VERSION 5.7 ;
  NOWIREEXTENSIONATPIN ON ;
  DIVIDERCHAR "/" ;
  BUSBITCHARS "[]" ;
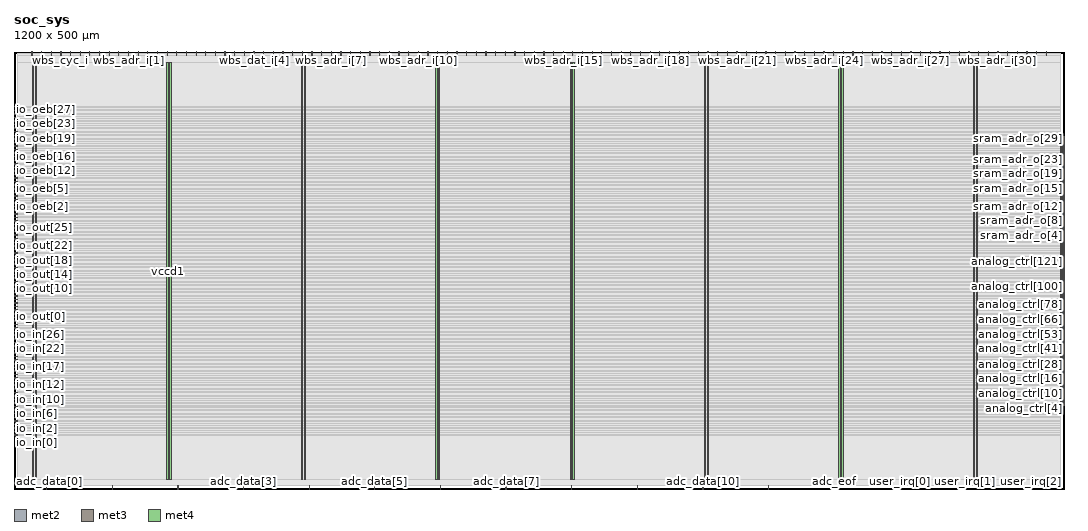
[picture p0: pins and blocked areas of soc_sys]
MACRO soc_sys
  CLASS BLOCK ;
  FOREIGN soc_sys ;
  ORIGIN 0.000 0.000 ;
  SIZE 1200.000 BY 500.000 ;
  PIN adc_data[0]
    DIRECTION INPUT ;
    USE SIGNAL ;
    ANTENNAGATEAREA 0.852000 ;
    PORT
      LAYER met2 ;
        RECT 37.350 0.000 37.630 4.000 ;
    END
  END adc_data[0]
  PIN adc_data[10]
    DIRECTION INPUT ;
    USE SIGNAL ;
    ANTENNAGATEAREA 0.247500 ;
    PORT
      LAYER met2 ;
        RECT 787.150 0.000 787.430 4.000 ;
    END
  END adc_data[10]
  PIN adc_data[11]
    DIRECTION INPUT ;
    USE SIGNAL ;
    ANTENNAGATEAREA 0.213000 ;
    PORT
      LAYER met2 ;
        RECT 862.130 0.000 862.410 4.000 ;
    END
  END adc_data[11]
  PIN adc_data[1]
    DIRECTION INPUT ;
    USE SIGNAL ;
    ANTENNAGATEAREA 0.742500 ;
    PORT
      LAYER met2 ;
        RECT 112.330 0.000 112.610 4.000 ;
    END
  END adc_data[1]
  PIN adc_data[2]
    DIRECTION INPUT ;
    USE SIGNAL ;
    ANTENNAGATEAREA 0.742500 ;
    PORT
      LAYER met2 ;
        RECT 187.310 0.000 187.590 4.000 ;
    END
  END adc_data[2]
  PIN adc_data[3]
    DIRECTION INPUT ;
    USE SIGNAL ;
    ANTENNAGATEAREA 0.742500 ;
    PORT
      LAYER met2 ;
        RECT 262.290 0.000 262.570 4.000 ;
    END
  END adc_data[3]
  PIN adc_data[4]
    DIRECTION INPUT ;
    USE SIGNAL ;
    ANTENNAGATEAREA 0.742500 ;
    PORT
      LAYER met2 ;
        RECT 337.270 0.000 337.550 4.000 ;
    END
  END adc_data[4]
  PIN adc_data[5]
    DIRECTION INPUT ;
    USE SIGNAL ;
    ANTENNAGATEAREA 0.495000 ;
    PORT
      LAYER met2 ;
        RECT 412.250 0.000 412.530 4.000 ;
    END
  END adc_data[5]
  PIN adc_data[6]
    DIRECTION INPUT ;
    USE SIGNAL ;
    ANTENNAGATEAREA 0.495000 ;
    PORT
      LAYER met2 ;
        RECT 487.230 0.000 487.510 4.000 ;
    END
  END adc_data[6]
  PIN adc_data[7]
    DIRECTION INPUT ;
    USE SIGNAL ;
    ANTENNAGATEAREA 0.426000 ;
    PORT
      LAYER met2 ;
        RECT 562.210 0.000 562.490 4.000 ;
    END
  END adc_data[7]
  PIN adc_data[8]
    DIRECTION INPUT ;
    USE SIGNAL ;
    ANTENNAGATEAREA 0.426000 ;
    PORT
      LAYER met2 ;
        RECT 637.190 0.000 637.470 4.000 ;
    END
  END adc_data[8]
  PIN adc_data[9]
    DIRECTION INPUT ;
    USE SIGNAL ;
    ANTENNAGATEAREA 0.247500 ;
    PORT
      LAYER met2 ;
        RECT 712.170 0.000 712.450 4.000 ;
    END
  END adc_data[9]
  PIN adc_eof
    DIRECTION INPUT ;
    USE SIGNAL ;
    ANTENNAGATEAREA 0.159000 ;
    PORT
      LAYER met2 ;
        RECT 937.110 0.000 937.390 4.000 ;
    END
  END adc_eof
  PIN analog_ctrl[0]
    DIRECTION OUTPUT ;
    USE SIGNAL ;
    ANTENNADIFFAREA 2.673000 ;
    PORT
      LAYER met3 ;
        RECT 1196.000 95.240 1200.000 95.840 ;
    END
  END analog_ctrl[0]
  PIN analog_ctrl[100]
    DIRECTION OUTPUT ;
    USE SIGNAL ;
    PORT
      LAYER met3 ;
        RECT 1196.000 231.240 1200.000 231.840 ;
    END
  END analog_ctrl[100]
  PIN analog_ctrl[101]
    DIRECTION OUTPUT ;
    USE SIGNAL ;
    PORT
      LAYER met3 ;
        RECT 1196.000 232.600 1200.000 233.200 ;
    END
  END analog_ctrl[101]
  PIN analog_ctrl[102]
    DIRECTION OUTPUT ;
    USE SIGNAL ;
    PORT
      LAYER met3 ;
        RECT 1196.000 233.960 1200.000 234.560 ;
    END
  END analog_ctrl[102]
  PIN analog_ctrl[103]
    DIRECTION OUTPUT ;
    USE SIGNAL ;
    PORT
      LAYER met3 ;
        RECT 1196.000 235.320 1200.000 235.920 ;
    END
  END analog_ctrl[103]
  PIN analog_ctrl[104]
    DIRECTION OUTPUT ;
    USE SIGNAL ;
    ANTENNADIFFAREA 2.673000 ;
    PORT
      LAYER met3 ;
        RECT 1196.000 236.680 1200.000 237.280 ;
    END
  END analog_ctrl[104]
  PIN analog_ctrl[105]
    DIRECTION OUTPUT ;
    USE SIGNAL ;
    ANTENNADIFFAREA 2.673000 ;
    PORT
      LAYER met3 ;
        RECT 1196.000 238.040 1200.000 238.640 ;
    END
  END analog_ctrl[105]
  PIN analog_ctrl[106]
    DIRECTION OUTPUT ;
    USE SIGNAL ;
    ANTENNADIFFAREA 2.673000 ;
    PORT
      LAYER met3 ;
        RECT 1196.000 239.400 1200.000 240.000 ;
    END
  END analog_ctrl[106]
  PIN analog_ctrl[107]
    DIRECTION OUTPUT ;
    USE SIGNAL ;
    ANTENNADIFFAREA 2.673000 ;
    PORT
      LAYER met3 ;
        RECT 1196.000 240.760 1200.000 241.360 ;
    END
  END analog_ctrl[107]
  PIN analog_ctrl[108]
    DIRECTION OUTPUT ;
    USE SIGNAL ;
    ANTENNADIFFAREA 2.673000 ;
    PORT
      LAYER met3 ;
        RECT 1196.000 242.120 1200.000 242.720 ;
    END
  END analog_ctrl[108]
  PIN analog_ctrl[109]
    DIRECTION OUTPUT ;
    USE SIGNAL ;
    ANTENNADIFFAREA 2.673000 ;
    PORT
      LAYER met3 ;
        RECT 1196.000 243.480 1200.000 244.080 ;
    END
  END analog_ctrl[109]
  PIN analog_ctrl[10]
    DIRECTION OUTPUT ;
    USE SIGNAL ;
    ANTENNADIFFAREA 2.673000 ;
    PORT
      LAYER met3 ;
        RECT 1196.000 108.840 1200.000 109.440 ;
    END
  END analog_ctrl[10]
  PIN analog_ctrl[110]
    DIRECTION OUTPUT ;
    USE SIGNAL ;
    ANTENNADIFFAREA 2.673000 ;
    PORT
      LAYER met3 ;
        RECT 1196.000 244.840 1200.000 245.440 ;
    END
  END analog_ctrl[110]
  PIN analog_ctrl[111]
    DIRECTION OUTPUT ;
    USE SIGNAL ;
    ANTENNADIFFAREA 2.673000 ;
    PORT
      LAYER met3 ;
        RECT 1196.000 246.200 1200.000 246.800 ;
    END
  END analog_ctrl[111]
  PIN analog_ctrl[112]
    DIRECTION OUTPUT ;
    USE SIGNAL ;
    ANTENNADIFFAREA 2.673000 ;
    PORT
      LAYER met3 ;
        RECT 1196.000 247.560 1200.000 248.160 ;
    END
  END analog_ctrl[112]
  PIN analog_ctrl[113]
    DIRECTION OUTPUT ;
    USE SIGNAL ;
    ANTENNADIFFAREA 2.673000 ;
    PORT
      LAYER met3 ;
        RECT 1196.000 248.920 1200.000 249.520 ;
    END
  END analog_ctrl[113]
  PIN analog_ctrl[114]
    DIRECTION OUTPUT ;
    USE SIGNAL ;
    ANTENNADIFFAREA 2.673000 ;
    PORT
      LAYER met3 ;
        RECT 1196.000 250.280 1200.000 250.880 ;
    END
  END analog_ctrl[114]
  PIN analog_ctrl[115]
    DIRECTION OUTPUT ;
    USE SIGNAL ;
    ANTENNADIFFAREA 2.673000 ;
    PORT
      LAYER met3 ;
        RECT 1196.000 251.640 1200.000 252.240 ;
    END
  END analog_ctrl[115]
  PIN analog_ctrl[116]
    DIRECTION OUTPUT ;
    USE SIGNAL ;
    ANTENNADIFFAREA 2.673000 ;
    PORT
      LAYER met3 ;
        RECT 1196.000 253.000 1200.000 253.600 ;
    END
  END analog_ctrl[116]
  PIN analog_ctrl[117]
    DIRECTION OUTPUT ;
    USE SIGNAL ;
    ANTENNADIFFAREA 2.673000 ;
    PORT
      LAYER met3 ;
        RECT 1196.000 254.360 1200.000 254.960 ;
    END
  END analog_ctrl[117]
  PIN analog_ctrl[118]
    DIRECTION OUTPUT ;
    USE SIGNAL ;
    ANTENNADIFFAREA 2.673000 ;
    PORT
      LAYER met3 ;
        RECT 1196.000 255.720 1200.000 256.320 ;
    END
  END analog_ctrl[118]
  PIN analog_ctrl[119]
    DIRECTION OUTPUT ;
    USE SIGNAL ;
    ANTENNADIFFAREA 2.673000 ;
    PORT
      LAYER met3 ;
        RECT 1196.000 257.080 1200.000 257.680 ;
    END
  END analog_ctrl[119]
  PIN analog_ctrl[11]
    DIRECTION OUTPUT ;
    USE SIGNAL ;
    ANTENNADIFFAREA 2.673000 ;
    PORT
      LAYER met3 ;
        RECT 1196.000 110.200 1200.000 110.800 ;
    END
  END analog_ctrl[11]
  PIN analog_ctrl[120]
    DIRECTION OUTPUT ;
    USE SIGNAL ;
    ANTENNADIFFAREA 2.673000 ;
    PORT
      LAYER met3 ;
        RECT 1196.000 258.440 1200.000 259.040 ;
    END
  END analog_ctrl[120]
  PIN analog_ctrl[121]
    DIRECTION OUTPUT ;
    USE SIGNAL ;
    ANTENNADIFFAREA 2.673000 ;
    PORT
      LAYER met3 ;
        RECT 1196.000 259.800 1200.000 260.400 ;
    END
  END analog_ctrl[121]
  PIN analog_ctrl[122]
    DIRECTION OUTPUT ;
    USE SIGNAL ;
    ANTENNADIFFAREA 2.673000 ;
    PORT
      LAYER met3 ;
        RECT 1196.000 261.160 1200.000 261.760 ;
    END
  END analog_ctrl[122]
  PIN analog_ctrl[12]
    DIRECTION OUTPUT ;
    USE SIGNAL ;
    ANTENNADIFFAREA 2.673000 ;
    PORT
      LAYER met3 ;
        RECT 1196.000 111.560 1200.000 112.160 ;
    END
  END analog_ctrl[12]
  PIN analog_ctrl[13]
    DIRECTION OUTPUT ;
    USE SIGNAL ;
    ANTENNADIFFAREA 2.673000 ;
    PORT
      LAYER met3 ;
        RECT 1196.000 112.920 1200.000 113.520 ;
    END
  END analog_ctrl[13]
  PIN analog_ctrl[14]
    DIRECTION OUTPUT ;
    USE SIGNAL ;
    ANTENNADIFFAREA 2.673000 ;
    PORT
      LAYER met3 ;
        RECT 1196.000 114.280 1200.000 114.880 ;
    END
  END analog_ctrl[14]
  PIN analog_ctrl[15]
    DIRECTION OUTPUT ;
    USE SIGNAL ;
    ANTENNADIFFAREA 2.673000 ;
    PORT
      LAYER met3 ;
        RECT 1196.000 115.640 1200.000 116.240 ;
    END
  END analog_ctrl[15]
  PIN analog_ctrl[16]
    DIRECTION OUTPUT ;
    USE SIGNAL ;
    ANTENNADIFFAREA 2.673000 ;
    PORT
      LAYER met3 ;
        RECT 1196.000 117.000 1200.000 117.600 ;
    END
  END analog_ctrl[16]
  PIN analog_ctrl[17]
    DIRECTION OUTPUT ;
    USE SIGNAL ;
    ANTENNADIFFAREA 2.673000 ;
    PORT
      LAYER met3 ;
        RECT 1196.000 118.360 1200.000 118.960 ;
    END
  END analog_ctrl[17]
  PIN analog_ctrl[18]
    DIRECTION OUTPUT ;
    USE SIGNAL ;
    ANTENNADIFFAREA 2.673000 ;
    PORT
      LAYER met3 ;
        RECT 1196.000 119.720 1200.000 120.320 ;
    END
  END analog_ctrl[18]
  PIN analog_ctrl[19]
    DIRECTION OUTPUT ;
    USE SIGNAL ;
    ANTENNADIFFAREA 2.673000 ;
    PORT
      LAYER met3 ;
        RECT 1196.000 121.080 1200.000 121.680 ;
    END
  END analog_ctrl[19]
  PIN analog_ctrl[1]
    DIRECTION OUTPUT ;
    USE SIGNAL ;
    ANTENNADIFFAREA 2.673000 ;
    PORT
      LAYER met3 ;
        RECT 1196.000 96.600 1200.000 97.200 ;
    END
  END analog_ctrl[1]
  PIN analog_ctrl[20]
    DIRECTION OUTPUT ;
    USE SIGNAL ;
    ANTENNADIFFAREA 2.673000 ;
    PORT
      LAYER met3 ;
        RECT 1196.000 122.440 1200.000 123.040 ;
    END
  END analog_ctrl[20]
  PIN analog_ctrl[21]
    DIRECTION OUTPUT ;
    USE SIGNAL ;
    ANTENNADIFFAREA 2.673000 ;
    PORT
      LAYER met3 ;
        RECT 1196.000 123.800 1200.000 124.400 ;
    END
  END analog_ctrl[21]
  PIN analog_ctrl[22]
    DIRECTION OUTPUT ;
    USE SIGNAL ;
    ANTENNADIFFAREA 2.673000 ;
    PORT
      LAYER met3 ;
        RECT 1196.000 125.160 1200.000 125.760 ;
    END
  END analog_ctrl[22]
  PIN analog_ctrl[23]
    DIRECTION OUTPUT ;
    USE SIGNAL ;
    ANTENNADIFFAREA 2.673000 ;
    PORT
      LAYER met3 ;
        RECT 1196.000 126.520 1200.000 127.120 ;
    END
  END analog_ctrl[23]
  PIN analog_ctrl[24]
    DIRECTION OUTPUT ;
    USE SIGNAL ;
    ANTENNADIFFAREA 2.673000 ;
    PORT
      LAYER met3 ;
        RECT 1196.000 127.880 1200.000 128.480 ;
    END
  END analog_ctrl[24]
  PIN analog_ctrl[25]
    DIRECTION OUTPUT ;
    USE SIGNAL ;
    ANTENNADIFFAREA 2.673000 ;
    PORT
      LAYER met3 ;
        RECT 1196.000 129.240 1200.000 129.840 ;
    END
  END analog_ctrl[25]
  PIN analog_ctrl[26]
    DIRECTION OUTPUT ;
    USE SIGNAL ;
    ANTENNADIFFAREA 2.673000 ;
    PORT
      LAYER met3 ;
        RECT 1196.000 130.600 1200.000 131.200 ;
    END
  END analog_ctrl[26]
  PIN analog_ctrl[27]
    DIRECTION OUTPUT ;
    USE SIGNAL ;
    ANTENNADIFFAREA 2.673000 ;
    PORT
      LAYER met3 ;
        RECT 1196.000 131.960 1200.000 132.560 ;
    END
  END analog_ctrl[27]
  PIN analog_ctrl[28]
    DIRECTION OUTPUT ;
    USE SIGNAL ;
    ANTENNADIFFAREA 2.673000 ;
    PORT
      LAYER met3 ;
        RECT 1196.000 133.320 1200.000 133.920 ;
    END
  END analog_ctrl[28]
  PIN analog_ctrl[29]
    DIRECTION OUTPUT ;
    USE SIGNAL ;
    ANTENNADIFFAREA 2.673000 ;
    PORT
      LAYER met3 ;
        RECT 1196.000 134.680 1200.000 135.280 ;
    END
  END analog_ctrl[29]
  PIN analog_ctrl[2]
    DIRECTION OUTPUT ;
    USE SIGNAL ;
    ANTENNADIFFAREA 2.673000 ;
    PORT
      LAYER met3 ;
        RECT 1196.000 97.960 1200.000 98.560 ;
    END
  END analog_ctrl[2]
  PIN analog_ctrl[30]
    DIRECTION OUTPUT ;
    USE SIGNAL ;
    ANTENNADIFFAREA 2.673000 ;
    PORT
      LAYER met3 ;
        RECT 1196.000 136.040 1200.000 136.640 ;
    END
  END analog_ctrl[30]
  PIN analog_ctrl[31]
    DIRECTION OUTPUT ;
    USE SIGNAL ;
    ANTENNADIFFAREA 2.673000 ;
    PORT
      LAYER met3 ;
        RECT 1196.000 137.400 1200.000 138.000 ;
    END
  END analog_ctrl[31]
  PIN analog_ctrl[32]
    DIRECTION OUTPUT ;
    USE SIGNAL ;
    ANTENNADIFFAREA 2.673000 ;
    PORT
      LAYER met3 ;
        RECT 1196.000 138.760 1200.000 139.360 ;
    END
  END analog_ctrl[32]
  PIN analog_ctrl[33]
    DIRECTION OUTPUT ;
    USE SIGNAL ;
    ANTENNADIFFAREA 2.673000 ;
    PORT
      LAYER met3 ;
        RECT 1196.000 140.120 1200.000 140.720 ;
    END
  END analog_ctrl[33]
  PIN analog_ctrl[34]
    DIRECTION OUTPUT ;
    USE SIGNAL ;
    ANTENNADIFFAREA 2.673000 ;
    PORT
      LAYER met3 ;
        RECT 1196.000 141.480 1200.000 142.080 ;
    END
  END analog_ctrl[34]
  PIN analog_ctrl[35]
    DIRECTION OUTPUT ;
    USE SIGNAL ;
    ANTENNADIFFAREA 2.673000 ;
    PORT
      LAYER met3 ;
        RECT 1196.000 142.840 1200.000 143.440 ;
    END
  END analog_ctrl[35]
  PIN analog_ctrl[36]
    DIRECTION OUTPUT ;
    USE SIGNAL ;
    ANTENNADIFFAREA 2.673000 ;
    PORT
      LAYER met3 ;
        RECT 1196.000 144.200 1200.000 144.800 ;
    END
  END analog_ctrl[36]
  PIN analog_ctrl[37]
    DIRECTION OUTPUT ;
    USE SIGNAL ;
    ANTENNADIFFAREA 2.673000 ;
    PORT
      LAYER met3 ;
        RECT 1196.000 145.560 1200.000 146.160 ;
    END
  END analog_ctrl[37]
  PIN analog_ctrl[38]
    DIRECTION OUTPUT ;
    USE SIGNAL ;
    ANTENNADIFFAREA 2.673000 ;
    PORT
      LAYER met3 ;
        RECT 1196.000 146.920 1200.000 147.520 ;
    END
  END analog_ctrl[38]
  PIN analog_ctrl[39]
    DIRECTION OUTPUT ;
    USE SIGNAL ;
    ANTENNADIFFAREA 2.673000 ;
    PORT
      LAYER met3 ;
        RECT 1196.000 148.280 1200.000 148.880 ;
    END
  END analog_ctrl[39]
  PIN analog_ctrl[3]
    DIRECTION OUTPUT ;
    USE SIGNAL ;
    ANTENNADIFFAREA 2.673000 ;
    PORT
      LAYER met3 ;
        RECT 1196.000 99.320 1200.000 99.920 ;
    END
  END analog_ctrl[3]
  PIN analog_ctrl[40]
    DIRECTION OUTPUT ;
    USE SIGNAL ;
    ANTENNADIFFAREA 2.673000 ;
    PORT
      LAYER met3 ;
        RECT 1196.000 149.640 1200.000 150.240 ;
    END
  END analog_ctrl[40]
  PIN analog_ctrl[41]
    DIRECTION OUTPUT ;
    USE SIGNAL ;
    ANTENNADIFFAREA 2.673000 ;
    PORT
      LAYER met3 ;
        RECT 1196.000 151.000 1200.000 151.600 ;
    END
  END analog_ctrl[41]
  PIN analog_ctrl[42]
    DIRECTION OUTPUT ;
    USE SIGNAL ;
    ANTENNADIFFAREA 2.673000 ;
    PORT
      LAYER met3 ;
        RECT 1196.000 152.360 1200.000 152.960 ;
    END
  END analog_ctrl[42]
  PIN analog_ctrl[43]
    DIRECTION OUTPUT ;
    USE SIGNAL ;
    ANTENNADIFFAREA 2.673000 ;
    PORT
      LAYER met3 ;
        RECT 1196.000 153.720 1200.000 154.320 ;
    END
  END analog_ctrl[43]
  PIN analog_ctrl[44]
    DIRECTION OUTPUT ;
    USE SIGNAL ;
    ANTENNADIFFAREA 2.673000 ;
    PORT
      LAYER met3 ;
        RECT 1196.000 155.080 1200.000 155.680 ;
    END
  END analog_ctrl[44]
  PIN analog_ctrl[45]
    DIRECTION OUTPUT ;
    USE SIGNAL ;
    ANTENNADIFFAREA 2.673000 ;
    PORT
      LAYER met3 ;
        RECT 1196.000 156.440 1200.000 157.040 ;
    END
  END analog_ctrl[45]
  PIN analog_ctrl[46]
    DIRECTION OUTPUT ;
    USE SIGNAL ;
    ANTENNADIFFAREA 2.673000 ;
    PORT
      LAYER met3 ;
        RECT 1196.000 157.800 1200.000 158.400 ;
    END
  END analog_ctrl[46]
  PIN analog_ctrl[47]
    DIRECTION OUTPUT ;
    USE SIGNAL ;
    ANTENNADIFFAREA 2.673000 ;
    PORT
      LAYER met3 ;
        RECT 1196.000 159.160 1200.000 159.760 ;
    END
  END analog_ctrl[47]
  PIN analog_ctrl[48]
    DIRECTION OUTPUT ;
    USE SIGNAL ;
    ANTENNADIFFAREA 2.673000 ;
    PORT
      LAYER met3 ;
        RECT 1196.000 160.520 1200.000 161.120 ;
    END
  END analog_ctrl[48]
  PIN analog_ctrl[49]
    DIRECTION OUTPUT ;
    USE SIGNAL ;
    ANTENNADIFFAREA 2.673000 ;
    PORT
      LAYER met3 ;
        RECT 1196.000 161.880 1200.000 162.480 ;
    END
  END analog_ctrl[49]
  PIN analog_ctrl[4]
    DIRECTION OUTPUT ;
    USE SIGNAL ;
    ANTENNADIFFAREA 2.673000 ;
    PORT
      LAYER met3 ;
        RECT 1196.000 100.680 1200.000 101.280 ;
    END
  END analog_ctrl[4]
  PIN analog_ctrl[50]
    DIRECTION OUTPUT ;
    USE SIGNAL ;
    ANTENNADIFFAREA 2.673000 ;
    PORT
      LAYER met3 ;
        RECT 1196.000 163.240 1200.000 163.840 ;
    END
  END analog_ctrl[50]
  PIN analog_ctrl[51]
    DIRECTION OUTPUT ;
    USE SIGNAL ;
    ANTENNADIFFAREA 2.673000 ;
    PORT
      LAYER met3 ;
        RECT 1196.000 164.600 1200.000 165.200 ;
    END
  END analog_ctrl[51]
  PIN analog_ctrl[52]
    DIRECTION OUTPUT ;
    USE SIGNAL ;
    ANTENNADIFFAREA 2.673000 ;
    PORT
      LAYER met3 ;
        RECT 1196.000 165.960 1200.000 166.560 ;
    END
  END analog_ctrl[52]
  PIN analog_ctrl[53]
    DIRECTION OUTPUT ;
    USE SIGNAL ;
    ANTENNADIFFAREA 2.673000 ;
    PORT
      LAYER met3 ;
        RECT 1196.000 167.320 1200.000 167.920 ;
    END
  END analog_ctrl[53]
  PIN analog_ctrl[54]
    DIRECTION OUTPUT ;
    USE SIGNAL ;
    ANTENNADIFFAREA 2.673000 ;
    PORT
      LAYER met3 ;
        RECT 1196.000 168.680 1200.000 169.280 ;
    END
  END analog_ctrl[54]
  PIN analog_ctrl[55]
    DIRECTION OUTPUT ;
    USE SIGNAL ;
    ANTENNADIFFAREA 2.673000 ;
    PORT
      LAYER met3 ;
        RECT 1196.000 170.040 1200.000 170.640 ;
    END
  END analog_ctrl[55]
  PIN analog_ctrl[56]
    DIRECTION OUTPUT ;
    USE SIGNAL ;
    ANTENNADIFFAREA 2.673000 ;
    PORT
      LAYER met3 ;
        RECT 1196.000 171.400 1200.000 172.000 ;
    END
  END analog_ctrl[56]
  PIN analog_ctrl[57]
    DIRECTION OUTPUT ;
    USE SIGNAL ;
    ANTENNADIFFAREA 2.673000 ;
    PORT
      LAYER met3 ;
        RECT 1196.000 172.760 1200.000 173.360 ;
    END
  END analog_ctrl[57]
  PIN analog_ctrl[58]
    DIRECTION OUTPUT ;
    USE SIGNAL ;
    ANTENNADIFFAREA 2.673000 ;
    PORT
      LAYER met3 ;
        RECT 1196.000 174.120 1200.000 174.720 ;
    END
  END analog_ctrl[58]
  PIN analog_ctrl[59]
    DIRECTION OUTPUT ;
    USE SIGNAL ;
    ANTENNADIFFAREA 2.673000 ;
    PORT
      LAYER met3 ;
        RECT 1196.000 175.480 1200.000 176.080 ;
    END
  END analog_ctrl[59]
  PIN analog_ctrl[5]
    DIRECTION OUTPUT ;
    USE SIGNAL ;
    ANTENNADIFFAREA 2.673000 ;
    PORT
      LAYER met3 ;
        RECT 1196.000 102.040 1200.000 102.640 ;
    END
  END analog_ctrl[5]
  PIN analog_ctrl[60]
    DIRECTION OUTPUT ;
    USE SIGNAL ;
    ANTENNADIFFAREA 2.673000 ;
    PORT
      LAYER met3 ;
        RECT 1196.000 176.840 1200.000 177.440 ;
    END
  END analog_ctrl[60]
  PIN analog_ctrl[61]
    DIRECTION OUTPUT ;
    USE SIGNAL ;
    ANTENNADIFFAREA 2.673000 ;
    PORT
      LAYER met3 ;
        RECT 1196.000 178.200 1200.000 178.800 ;
    END
  END analog_ctrl[61]
  PIN analog_ctrl[62]
    DIRECTION OUTPUT ;
    USE SIGNAL ;
    ANTENNADIFFAREA 2.673000 ;
    PORT
      LAYER met3 ;
        RECT 1196.000 179.560 1200.000 180.160 ;
    END
  END analog_ctrl[62]
  PIN analog_ctrl[63]
    DIRECTION OUTPUT ;
    USE SIGNAL ;
    ANTENNADIFFAREA 2.673000 ;
    PORT
      LAYER met3 ;
        RECT 1196.000 180.920 1200.000 181.520 ;
    END
  END analog_ctrl[63]
  PIN analog_ctrl[64]
    DIRECTION OUTPUT ;
    USE SIGNAL ;
    ANTENNADIFFAREA 2.673000 ;
    PORT
      LAYER met3 ;
        RECT 1196.000 182.280 1200.000 182.880 ;
    END
  END analog_ctrl[64]
  PIN analog_ctrl[65]
    DIRECTION OUTPUT ;
    USE SIGNAL ;
    ANTENNADIFFAREA 2.673000 ;
    PORT
      LAYER met3 ;
        RECT 1196.000 183.640 1200.000 184.240 ;
    END
  END analog_ctrl[65]
  PIN analog_ctrl[66]
    DIRECTION OUTPUT ;
    USE SIGNAL ;
    ANTENNADIFFAREA 2.673000 ;
    PORT
      LAYER met3 ;
        RECT 1196.000 185.000 1200.000 185.600 ;
    END
  END analog_ctrl[66]
  PIN analog_ctrl[67]
    DIRECTION OUTPUT ;
    USE SIGNAL ;
    ANTENNADIFFAREA 2.673000 ;
    PORT
      LAYER met3 ;
        RECT 1196.000 186.360 1200.000 186.960 ;
    END
  END analog_ctrl[67]
  PIN analog_ctrl[68]
    DIRECTION OUTPUT ;
    USE SIGNAL ;
    ANTENNADIFFAREA 2.673000 ;
    PORT
      LAYER met3 ;
        RECT 1196.000 187.720 1200.000 188.320 ;
    END
  END analog_ctrl[68]
  PIN analog_ctrl[69]
    DIRECTION OUTPUT ;
    USE SIGNAL ;
    ANTENNADIFFAREA 2.673000 ;
    PORT
      LAYER met3 ;
        RECT 1196.000 189.080 1200.000 189.680 ;
    END
  END analog_ctrl[69]
  PIN analog_ctrl[6]
    DIRECTION OUTPUT ;
    USE SIGNAL ;
    ANTENNADIFFAREA 2.673000 ;
    PORT
      LAYER met3 ;
        RECT 1196.000 103.400 1200.000 104.000 ;
    END
  END analog_ctrl[6]
  PIN analog_ctrl[70]
    DIRECTION OUTPUT ;
    USE SIGNAL ;
    ANTENNADIFFAREA 2.673000 ;
    PORT
      LAYER met3 ;
        RECT 1196.000 190.440 1200.000 191.040 ;
    END
  END analog_ctrl[70]
  PIN analog_ctrl[71]
    DIRECTION OUTPUT ;
    USE SIGNAL ;
    ANTENNADIFFAREA 2.673000 ;
    PORT
      LAYER met3 ;
        RECT 1196.000 191.800 1200.000 192.400 ;
    END
  END analog_ctrl[71]
  PIN analog_ctrl[72]
    DIRECTION OUTPUT ;
    USE SIGNAL ;
    ANTENNADIFFAREA 2.673000 ;
    PORT
      LAYER met3 ;
        RECT 1196.000 193.160 1200.000 193.760 ;
    END
  END analog_ctrl[72]
  PIN analog_ctrl[73]
    DIRECTION OUTPUT ;
    USE SIGNAL ;
    ANTENNADIFFAREA 2.673000 ;
    PORT
      LAYER met3 ;
        RECT 1196.000 194.520 1200.000 195.120 ;
    END
  END analog_ctrl[73]
  PIN analog_ctrl[74]
    DIRECTION OUTPUT ;
    USE SIGNAL ;
    ANTENNADIFFAREA 2.673000 ;
    PORT
      LAYER met3 ;
        RECT 1196.000 195.880 1200.000 196.480 ;
    END
  END analog_ctrl[74]
  PIN analog_ctrl[75]
    DIRECTION OUTPUT ;
    USE SIGNAL ;
    ANTENNADIFFAREA 2.673000 ;
    PORT
      LAYER met3 ;
        RECT 1196.000 197.240 1200.000 197.840 ;
    END
  END analog_ctrl[75]
  PIN analog_ctrl[76]
    DIRECTION OUTPUT ;
    USE SIGNAL ;
    ANTENNADIFFAREA 2.673000 ;
    PORT
      LAYER met3 ;
        RECT 1196.000 198.600 1200.000 199.200 ;
    END
  END analog_ctrl[76]
  PIN analog_ctrl[77]
    DIRECTION OUTPUT ;
    USE SIGNAL ;
    ANTENNADIFFAREA 2.673000 ;
    PORT
      LAYER met3 ;
        RECT 1196.000 199.960 1200.000 200.560 ;
    END
  END analog_ctrl[77]
  PIN analog_ctrl[78]
    DIRECTION OUTPUT ;
    USE SIGNAL ;
    ANTENNADIFFAREA 2.673000 ;
    PORT
      LAYER met3 ;
        RECT 1196.000 201.320 1200.000 201.920 ;
    END
  END analog_ctrl[78]
  PIN analog_ctrl[79]
    DIRECTION OUTPUT ;
    USE SIGNAL ;
    ANTENNADIFFAREA 2.673000 ;
    PORT
      LAYER met3 ;
        RECT 1196.000 202.680 1200.000 203.280 ;
    END
  END analog_ctrl[79]
  PIN analog_ctrl[7]
    DIRECTION OUTPUT ;
    USE SIGNAL ;
    PORT
      LAYER met3 ;
        RECT 1196.000 104.760 1200.000 105.360 ;
    END
  END analog_ctrl[7]
  PIN analog_ctrl[80]
    DIRECTION OUTPUT ;
    USE SIGNAL ;
    ANTENNADIFFAREA 2.673000 ;
    PORT
      LAYER met3 ;
        RECT 1196.000 204.040 1200.000 204.640 ;
    END
  END analog_ctrl[80]
  PIN analog_ctrl[81]
    DIRECTION OUTPUT ;
    USE SIGNAL ;
    ANTENNADIFFAREA 2.673000 ;
    PORT
      LAYER met3 ;
        RECT 1196.000 205.400 1200.000 206.000 ;
    END
  END analog_ctrl[81]
  PIN analog_ctrl[82]
    DIRECTION OUTPUT ;
    USE SIGNAL ;
    ANTENNADIFFAREA 2.673000 ;
    PORT
      LAYER met3 ;
        RECT 1196.000 206.760 1200.000 207.360 ;
    END
  END analog_ctrl[82]
  PIN analog_ctrl[83]
    DIRECTION OUTPUT ;
    USE SIGNAL ;
    ANTENNADIFFAREA 2.673000 ;
    PORT
      LAYER met3 ;
        RECT 1196.000 208.120 1200.000 208.720 ;
    END
  END analog_ctrl[83]
  PIN analog_ctrl[84]
    DIRECTION OUTPUT ;
    USE SIGNAL ;
    ANTENNADIFFAREA 2.673000 ;
    PORT
      LAYER met3 ;
        RECT 1196.000 209.480 1200.000 210.080 ;
    END
  END analog_ctrl[84]
  PIN analog_ctrl[85]
    DIRECTION OUTPUT ;
    USE SIGNAL ;
    ANTENNADIFFAREA 2.673000 ;
    PORT
      LAYER met3 ;
        RECT 1196.000 210.840 1200.000 211.440 ;
    END
  END analog_ctrl[85]
  PIN analog_ctrl[86]
    DIRECTION OUTPUT ;
    USE SIGNAL ;
    ANTENNADIFFAREA 2.673000 ;
    PORT
      LAYER met3 ;
        RECT 1196.000 212.200 1200.000 212.800 ;
    END
  END analog_ctrl[86]
  PIN analog_ctrl[87]
    DIRECTION OUTPUT ;
    USE SIGNAL ;
    ANTENNADIFFAREA 2.673000 ;
    PORT
      LAYER met3 ;
        RECT 1196.000 213.560 1200.000 214.160 ;
    END
  END analog_ctrl[87]
  PIN analog_ctrl[88]
    DIRECTION OUTPUT ;
    USE SIGNAL ;
    ANTENNADIFFAREA 2.673000 ;
    PORT
      LAYER met3 ;
        RECT 1196.000 214.920 1200.000 215.520 ;
    END
  END analog_ctrl[88]
  PIN analog_ctrl[89]
    DIRECTION OUTPUT ;
    USE SIGNAL ;
    ANTENNADIFFAREA 2.673000 ;
    PORT
      LAYER met3 ;
        RECT 1196.000 216.280 1200.000 216.880 ;
    END
  END analog_ctrl[89]
  PIN analog_ctrl[8]
    DIRECTION OUTPUT ;
    USE SIGNAL ;
    ANTENNADIFFAREA 2.673000 ;
    PORT
      LAYER met3 ;
        RECT 1196.000 106.120 1200.000 106.720 ;
    END
  END analog_ctrl[8]
  PIN analog_ctrl[90]
    DIRECTION OUTPUT ;
    USE SIGNAL ;
    ANTENNADIFFAREA 2.673000 ;
    PORT
      LAYER met3 ;
        RECT 1196.000 217.640 1200.000 218.240 ;
    END
  END analog_ctrl[90]
  PIN analog_ctrl[91]
    DIRECTION OUTPUT ;
    USE SIGNAL ;
    ANTENNADIFFAREA 2.673000 ;
    PORT
      LAYER met3 ;
        RECT 1196.000 219.000 1200.000 219.600 ;
    END
  END analog_ctrl[91]
  PIN analog_ctrl[92]
    DIRECTION OUTPUT ;
    USE SIGNAL ;
    ANTENNADIFFAREA 2.673000 ;
    PORT
      LAYER met3 ;
        RECT 1196.000 220.360 1200.000 220.960 ;
    END
  END analog_ctrl[92]
  PIN analog_ctrl[93]
    DIRECTION OUTPUT ;
    USE SIGNAL ;
    ANTENNADIFFAREA 2.673000 ;
    PORT
      LAYER met3 ;
        RECT 1196.000 221.720 1200.000 222.320 ;
    END
  END analog_ctrl[93]
  PIN analog_ctrl[94]
    DIRECTION OUTPUT ;
    USE SIGNAL ;
    ANTENNADIFFAREA 2.673000 ;
    PORT
      LAYER met3 ;
        RECT 1196.000 223.080 1200.000 223.680 ;
    END
  END analog_ctrl[94]
  PIN analog_ctrl[95]
    DIRECTION OUTPUT ;
    USE SIGNAL ;
    ANTENNADIFFAREA 2.673000 ;
    PORT
      LAYER met3 ;
        RECT 1196.000 224.440 1200.000 225.040 ;
    END
  END analog_ctrl[95]
  PIN analog_ctrl[96]
    DIRECTION OUTPUT ;
    USE SIGNAL ;
    ANTENNADIFFAREA 2.673000 ;
    PORT
      LAYER met3 ;
        RECT 1196.000 225.800 1200.000 226.400 ;
    END
  END analog_ctrl[96]
  PIN analog_ctrl[97]
    DIRECTION OUTPUT ;
    USE SIGNAL ;
    ANTENNADIFFAREA 2.673000 ;
    PORT
      LAYER met3 ;
        RECT 1196.000 227.160 1200.000 227.760 ;
    END
  END analog_ctrl[97]
  PIN analog_ctrl[98]
    DIRECTION OUTPUT ;
    USE SIGNAL ;
    PORT
      LAYER met3 ;
        RECT 1196.000 228.520 1200.000 229.120 ;
    END
  END analog_ctrl[98]
  PIN analog_ctrl[99]
    DIRECTION OUTPUT ;
    USE SIGNAL ;
    PORT
      LAYER met3 ;
        RECT 1196.000 229.880 1200.000 230.480 ;
    END
  END analog_ctrl[99]
  PIN analog_ctrl[9]
    DIRECTION OUTPUT ;
    USE SIGNAL ;
    ANTENNADIFFAREA 2.673000 ;
    PORT
      LAYER met3 ;
        RECT 1196.000 107.480 1200.000 108.080 ;
    END
  END analog_ctrl[9]
  PIN io_in[0]
    DIRECTION INPUT ;
    USE SIGNAL ;
    PORT
      LAYER met3 ;
        RECT 0.000 61.240 4.000 61.840 ;
    END
  END io_in[0]
  PIN io_in[10]
    DIRECTION INPUT ;
    USE SIGNAL ;
    PORT
      LAYER met3 ;
        RECT 0.000 102.040 4.000 102.640 ;
    END
  END io_in[10]
  PIN io_in[11]
    DIRECTION INPUT ;
    USE SIGNAL ;
    PORT
      LAYER met3 ;
        RECT 0.000 106.120 4.000 106.720 ;
    END
  END io_in[11]
  PIN io_in[12]
    DIRECTION INPUT ;
    USE SIGNAL ;
    PORT
      LAYER met3 ;
        RECT 0.000 110.200 4.000 110.800 ;
    END
  END io_in[12]
  PIN io_in[13]
    DIRECTION INPUT ;
    USE SIGNAL ;
    ANTENNAGATEAREA 0.426000 ;
    PORT
      LAYER met3 ;
        RECT 0.000 114.280 4.000 114.880 ;
    END
  END io_in[13]
  PIN io_in[14]
    DIRECTION INPUT ;
    USE SIGNAL ;
    ANTENNAGATEAREA 0.426000 ;
    PORT
      LAYER met3 ;
        RECT 0.000 118.360 4.000 118.960 ;
    END
  END io_in[14]
  PIN io_in[15]
    DIRECTION INPUT ;
    USE SIGNAL ;
    PORT
      LAYER met3 ;
        RECT 0.000 122.440 4.000 123.040 ;
    END
  END io_in[15]
  PIN io_in[16]
    DIRECTION INPUT ;
    USE SIGNAL ;
    ANTENNAGATEAREA 0.196500 ;
    PORT
      LAYER met3 ;
        RECT 0.000 126.520 4.000 127.120 ;
    END
  END io_in[16]
  PIN io_in[17]
    DIRECTION INPUT ;
    USE SIGNAL ;
    PORT
      LAYER met3 ;
        RECT 0.000 130.600 4.000 131.200 ;
    END
  END io_in[17]
  PIN io_in[18]
    DIRECTION INPUT ;
    USE SIGNAL ;
    PORT
      LAYER met3 ;
        RECT 0.000 134.680 4.000 135.280 ;
    END
  END io_in[18]
  PIN io_in[19]
    DIRECTION INPUT ;
    USE SIGNAL ;
    PORT
      LAYER met3 ;
        RECT 0.000 138.760 4.000 139.360 ;
    END
  END io_in[19]
  PIN io_in[1]
    DIRECTION INPUT ;
    USE SIGNAL ;
    PORT
      LAYER met3 ;
        RECT 0.000 65.320 4.000 65.920 ;
    END
  END io_in[1]
  PIN io_in[20]
    DIRECTION INPUT ;
    USE SIGNAL ;
    PORT
      LAYER met3 ;
        RECT 0.000 142.840 4.000 143.440 ;
    END
  END io_in[20]
  PIN io_in[21]
    DIRECTION INPUT ;
    USE SIGNAL ;
    PORT
      LAYER met3 ;
        RECT 0.000 146.920 4.000 147.520 ;
    END
  END io_in[21]
  PIN io_in[22]
    DIRECTION INPUT ;
    USE SIGNAL ;
    PORT
      LAYER met3 ;
        RECT 0.000 151.000 4.000 151.600 ;
    END
  END io_in[22]
  PIN io_in[23]
    DIRECTION INPUT ;
    USE SIGNAL ;
    PORT
      LAYER met3 ;
        RECT 0.000 155.080 4.000 155.680 ;
    END
  END io_in[23]
  PIN io_in[24]
    DIRECTION INPUT ;
    USE SIGNAL ;
    PORT
      LAYER met3 ;
        RECT 0.000 159.160 4.000 159.760 ;
    END
  END io_in[24]
  PIN io_in[25]
    DIRECTION INPUT ;
    USE SIGNAL ;
    PORT
      LAYER met3 ;
        RECT 0.000 163.240 4.000 163.840 ;
    END
  END io_in[25]
  PIN io_in[26]
    DIRECTION INPUT ;
    USE SIGNAL ;
    PORT
      LAYER met3 ;
        RECT 0.000 167.320 4.000 167.920 ;
    END
  END io_in[26]
  PIN io_in[27]
    DIRECTION INPUT ;
    USE SIGNAL ;
    PORT
      LAYER met3 ;
        RECT 0.000 171.400 4.000 172.000 ;
    END
  END io_in[27]
  PIN io_in[28]
    DIRECTION INPUT ;
    USE SIGNAL ;
    ANTENNAGATEAREA 0.742500 ;
    PORT
      LAYER met3 ;
        RECT 0.000 175.480 4.000 176.080 ;
    END
  END io_in[28]
  PIN io_in[29]
    DIRECTION INPUT ;
    USE SIGNAL ;
    ANTENNAGATEAREA 0.742500 ;
    PORT
      LAYER met3 ;
        RECT 0.000 179.560 4.000 180.160 ;
    END
  END io_in[29]
  PIN io_in[2]
    DIRECTION INPUT ;
    USE SIGNAL ;
    PORT
      LAYER met3 ;
        RECT 0.000 69.400 4.000 70.000 ;
    END
  END io_in[2]
  PIN io_in[30]
    DIRECTION INPUT ;
    USE SIGNAL ;
    ANTENNAGATEAREA 0.742500 ;
    PORT
      LAYER met3 ;
        RECT 0.000 183.640 4.000 184.240 ;
    END
  END io_in[30]
  PIN io_in[3]
    DIRECTION INPUT ;
    USE SIGNAL ;
    PORT
      LAYER met3 ;
        RECT 0.000 73.480 4.000 74.080 ;
    END
  END io_in[3]
  PIN io_in[4]
    DIRECTION INPUT ;
    USE SIGNAL ;
    PORT
      LAYER met3 ;
        RECT 0.000 77.560 4.000 78.160 ;
    END
  END io_in[4]
  PIN io_in[5]
    DIRECTION INPUT ;
    USE SIGNAL ;
    PORT
      LAYER met3 ;
        RECT 0.000 81.640 4.000 82.240 ;
    END
  END io_in[5]
  PIN io_in[6]
    DIRECTION INPUT ;
    USE SIGNAL ;
    PORT
      LAYER met3 ;
        RECT 0.000 85.720 4.000 86.320 ;
    END
  END io_in[6]
  PIN io_in[7]
    DIRECTION INPUT ;
    USE SIGNAL ;
    PORT
      LAYER met3 ;
        RECT 0.000 89.800 4.000 90.400 ;
    END
  END io_in[7]
  PIN io_in[8]
    DIRECTION INPUT ;
    USE SIGNAL ;
    PORT
      LAYER met3 ;
        RECT 0.000 93.880 4.000 94.480 ;
    END
  END io_in[8]
  PIN io_in[9]
    DIRECTION INPUT ;
    USE SIGNAL ;
    PORT
      LAYER met3 ;
        RECT 0.000 97.960 4.000 98.560 ;
    END
  END io_in[9]
  PIN io_oeb[0]
    DIRECTION OUTPUT ;
    USE SIGNAL ;
    PORT
      LAYER met3 ;
        RECT 0.000 314.200 4.000 314.800 ;
    END
  END io_oeb[0]
  PIN io_oeb[10]
    DIRECTION OUTPUT ;
    USE SIGNAL ;
    PORT
      LAYER met3 ;
        RECT 0.000 355.000 4.000 355.600 ;
    END
  END io_oeb[10]
  PIN io_oeb[11]
    DIRECTION OUTPUT ;
    USE SIGNAL ;
    PORT
      LAYER met3 ;
        RECT 0.000 359.080 4.000 359.680 ;
    END
  END io_oeb[11]
  PIN io_oeb[12]
    DIRECTION OUTPUT ;
    USE SIGNAL ;
    PORT
      LAYER met3 ;
        RECT 0.000 363.160 4.000 363.760 ;
    END
  END io_oeb[12]
  PIN io_oeb[13]
    DIRECTION OUTPUT ;
    USE SIGNAL ;
    ANTENNADIFFAREA 2.673000 ;
    PORT
      LAYER met3 ;
        RECT 0.000 367.240 4.000 367.840 ;
    END
  END io_oeb[13]
  PIN io_oeb[14]
    DIRECTION OUTPUT ;
    USE SIGNAL ;
    ANTENNADIFFAREA 2.673000 ;
    PORT
      LAYER met3 ;
        RECT 0.000 371.320 4.000 371.920 ;
    END
  END io_oeb[14]
  PIN io_oeb[15]
    DIRECTION OUTPUT ;
    USE SIGNAL ;
    PORT
      LAYER met3 ;
        RECT 0.000 375.400 4.000 376.000 ;
    END
  END io_oeb[15]
  PIN io_oeb[16]
    DIRECTION OUTPUT ;
    USE SIGNAL ;
    PORT
      LAYER met3 ;
        RECT 0.000 379.480 4.000 380.080 ;
    END
  END io_oeb[16]
  PIN io_oeb[17]
    DIRECTION OUTPUT ;
    USE SIGNAL ;
    PORT
      LAYER met3 ;
        RECT 0.000 383.560 4.000 384.160 ;
    END
  END io_oeb[17]
  PIN io_oeb[18]
    DIRECTION OUTPUT ;
    USE SIGNAL ;
    PORT
      LAYER met3 ;
        RECT 0.000 387.640 4.000 388.240 ;
    END
  END io_oeb[18]
  PIN io_oeb[19]
    DIRECTION OUTPUT ;
    USE SIGNAL ;
    PORT
      LAYER met3 ;
        RECT 0.000 391.720 4.000 392.320 ;
    END
  END io_oeb[19]
  PIN io_oeb[1]
    DIRECTION OUTPUT ;
    USE SIGNAL ;
    PORT
      LAYER met3 ;
        RECT 0.000 318.280 4.000 318.880 ;
    END
  END io_oeb[1]
  PIN io_oeb[20]
    DIRECTION OUTPUT ;
    USE SIGNAL ;
    PORT
      LAYER met3 ;
        RECT 0.000 395.800 4.000 396.400 ;
    END
  END io_oeb[20]
  PIN io_oeb[21]
    DIRECTION OUTPUT ;
    USE SIGNAL ;
    PORT
      LAYER met3 ;
        RECT 0.000 399.880 4.000 400.480 ;
    END
  END io_oeb[21]
  PIN io_oeb[22]
    DIRECTION OUTPUT ;
    USE SIGNAL ;
    PORT
      LAYER met3 ;
        RECT 0.000 403.960 4.000 404.560 ;
    END
  END io_oeb[22]
  PIN io_oeb[23]
    DIRECTION OUTPUT ;
    USE SIGNAL ;
    PORT
      LAYER met3 ;
        RECT 0.000 408.040 4.000 408.640 ;
    END
  END io_oeb[23]
  PIN io_oeb[24]
    DIRECTION OUTPUT ;
    USE SIGNAL ;
    PORT
      LAYER met3 ;
        RECT 0.000 412.120 4.000 412.720 ;
    END
  END io_oeb[24]
  PIN io_oeb[25]
    DIRECTION OUTPUT ;
    USE SIGNAL ;
    PORT
      LAYER met3 ;
        RECT 0.000 416.200 4.000 416.800 ;
    END
  END io_oeb[25]
  PIN io_oeb[26]
    DIRECTION OUTPUT ;
    USE SIGNAL ;
    PORT
      LAYER met3 ;
        RECT 0.000 420.280 4.000 420.880 ;
    END
  END io_oeb[26]
  PIN io_oeb[27]
    DIRECTION OUTPUT ;
    USE SIGNAL ;
    PORT
      LAYER met3 ;
        RECT 0.000 424.360 4.000 424.960 ;
    END
  END io_oeb[27]
  PIN io_oeb[28]
    DIRECTION OUTPUT ;
    USE SIGNAL ;
    ANTENNADIFFAREA 2.673000 ;
    PORT
      LAYER met3 ;
        RECT 0.000 428.440 4.000 429.040 ;
    END
  END io_oeb[28]
  PIN io_oeb[29]
    DIRECTION OUTPUT ;
    USE SIGNAL ;
    ANTENNADIFFAREA 2.673000 ;
    PORT
      LAYER met3 ;
        RECT 0.000 432.520 4.000 433.120 ;
    END
  END io_oeb[29]
  PIN io_oeb[2]
    DIRECTION OUTPUT ;
    USE SIGNAL ;
    PORT
      LAYER met3 ;
        RECT 0.000 322.360 4.000 322.960 ;
    END
  END io_oeb[2]
  PIN io_oeb[30]
    DIRECTION OUTPUT ;
    USE SIGNAL ;
    ANTENNADIFFAREA 2.673000 ;
    PORT
      LAYER met3 ;
        RECT 0.000 436.600 4.000 437.200 ;
    END
  END io_oeb[30]
  PIN io_oeb[3]
    DIRECTION OUTPUT ;
    USE SIGNAL ;
    PORT
      LAYER met3 ;
        RECT 0.000 326.440 4.000 327.040 ;
    END
  END io_oeb[3]
  PIN io_oeb[4]
    DIRECTION OUTPUT ;
    USE SIGNAL ;
    PORT
      LAYER met3 ;
        RECT 0.000 330.520 4.000 331.120 ;
    END
  END io_oeb[4]
  PIN io_oeb[5]
    DIRECTION OUTPUT ;
    USE SIGNAL ;
    PORT
      LAYER met3 ;
        RECT 0.000 334.600 4.000 335.200 ;
    END
  END io_oeb[5]
  PIN io_oeb[6]
    DIRECTION OUTPUT ;
    USE SIGNAL ;
    PORT
      LAYER met3 ;
        RECT 0.000 338.680 4.000 339.280 ;
    END
  END io_oeb[6]
  PIN io_oeb[7]
    DIRECTION OUTPUT ;
    USE SIGNAL ;
    PORT
      LAYER met3 ;
        RECT 0.000 342.760 4.000 343.360 ;
    END
  END io_oeb[7]
  PIN io_oeb[8]
    DIRECTION OUTPUT ;
    USE SIGNAL ;
    PORT
      LAYER met3 ;
        RECT 0.000 346.840 4.000 347.440 ;
    END
  END io_oeb[8]
  PIN io_oeb[9]
    DIRECTION OUTPUT ;
    USE SIGNAL ;
    PORT
      LAYER met3 ;
        RECT 0.000 350.920 4.000 351.520 ;
    END
  END io_oeb[9]
  PIN io_out[0]
    DIRECTION OUTPUT ;
    USE SIGNAL ;
    PORT
      LAYER met3 ;
        RECT 0.000 187.720 4.000 188.320 ;
    END
  END io_out[0]
  PIN io_out[10]
    DIRECTION OUTPUT ;
    USE SIGNAL ;
    ANTENNADIFFAREA 2.673000 ;
    PORT
      LAYER met3 ;
        RECT 0.000 228.520 4.000 229.120 ;
    END
  END io_out[10]
  PIN io_out[11]
    DIRECTION OUTPUT ;
    USE SIGNAL ;
    PORT
      LAYER met3 ;
        RECT 0.000 232.600 4.000 233.200 ;
    END
  END io_out[11]
  PIN io_out[12]
    DIRECTION OUTPUT ;
    USE SIGNAL ;
    ANTENNADIFFAREA 2.673000 ;
    PORT
      LAYER met3 ;
        RECT 0.000 236.680 4.000 237.280 ;
    END
  END io_out[12]
  PIN io_out[13]
    DIRECTION OUTPUT ;
    USE SIGNAL ;
    ANTENNADIFFAREA 2.673000 ;
    PORT
      LAYER met3 ;
        RECT 0.000 240.760 4.000 241.360 ;
    END
  END io_out[13]
  PIN io_out[14]
    DIRECTION OUTPUT ;
    USE SIGNAL ;
    ANTENNADIFFAREA 2.673000 ;
    PORT
      LAYER met3 ;
        RECT 0.000 244.840 4.000 245.440 ;
    END
  END io_out[14]
  PIN io_out[15]
    DIRECTION OUTPUT ;
    USE SIGNAL ;
    ANTENNADIFFAREA 2.673000 ;
    PORT
      LAYER met3 ;
        RECT 0.000 248.920 4.000 249.520 ;
    END
  END io_out[15]
  PIN io_out[16]
    DIRECTION OUTPUT ;
    USE SIGNAL ;
    PORT
      LAYER met3 ;
        RECT 0.000 253.000 4.000 253.600 ;
    END
  END io_out[16]
  PIN io_out[17]
    DIRECTION OUTPUT ;
    USE SIGNAL ;
    ANTENNADIFFAREA 2.673000 ;
    PORT
      LAYER met3 ;
        RECT 0.000 257.080 4.000 257.680 ;
    END
  END io_out[17]
  PIN io_out[18]
    DIRECTION OUTPUT ;
    USE SIGNAL ;
    ANTENNADIFFAREA 2.673000 ;
    PORT
      LAYER met3 ;
        RECT 0.000 261.160 4.000 261.760 ;
    END
  END io_out[18]
  PIN io_out[19]
    DIRECTION OUTPUT ;
    USE SIGNAL ;
    ANTENNADIFFAREA 2.673000 ;
    PORT
      LAYER met3 ;
        RECT 0.000 265.240 4.000 265.840 ;
    END
  END io_out[19]
  PIN io_out[1]
    DIRECTION OUTPUT ;
    USE SIGNAL ;
    PORT
      LAYER met3 ;
        RECT 0.000 191.800 4.000 192.400 ;
    END
  END io_out[1]
  PIN io_out[20]
    DIRECTION OUTPUT ;
    USE SIGNAL ;
    PORT
      LAYER met3 ;
        RECT 0.000 269.320 4.000 269.920 ;
    END
  END io_out[20]
  PIN io_out[21]
    DIRECTION OUTPUT ;
    USE SIGNAL ;
    PORT
      LAYER met3 ;
        RECT 0.000 273.400 4.000 274.000 ;
    END
  END io_out[21]
  PIN io_out[22]
    DIRECTION OUTPUT ;
    USE SIGNAL ;
    PORT
      LAYER met3 ;
        RECT 0.000 277.480 4.000 278.080 ;
    END
  END io_out[22]
  PIN io_out[23]
    DIRECTION OUTPUT ;
    USE SIGNAL ;
    ANTENNADIFFAREA 2.673000 ;
    PORT
      LAYER met3 ;
        RECT 0.000 281.560 4.000 282.160 ;
    END
  END io_out[23]
  PIN io_out[24]
    DIRECTION OUTPUT ;
    USE SIGNAL ;
    PORT
      LAYER met3 ;
        RECT 0.000 285.640 4.000 286.240 ;
    END
  END io_out[24]
  PIN io_out[25]
    DIRECTION OUTPUT ;
    USE SIGNAL ;
    PORT
      LAYER met3 ;
        RECT 0.000 289.720 4.000 290.320 ;
    END
  END io_out[25]
  PIN io_out[26]
    DIRECTION OUTPUT ;
    USE SIGNAL ;
    PORT
      LAYER met3 ;
        RECT 0.000 293.800 4.000 294.400 ;
    END
  END io_out[26]
  PIN io_out[27]
    DIRECTION OUTPUT ;
    USE SIGNAL ;
    PORT
      LAYER met3 ;
        RECT 0.000 297.880 4.000 298.480 ;
    END
  END io_out[27]
  PIN io_out[28]
    DIRECTION OUTPUT ;
    USE SIGNAL ;
    ANTENNADIFFAREA 2.673000 ;
    PORT
      LAYER met3 ;
        RECT 0.000 301.960 4.000 302.560 ;
    END
  END io_out[28]
  PIN io_out[29]
    DIRECTION OUTPUT ;
    USE SIGNAL ;
    ANTENNADIFFAREA 2.673000 ;
    PORT
      LAYER met3 ;
        RECT 0.000 306.040 4.000 306.640 ;
    END
  END io_out[29]
  PIN io_out[2]
    DIRECTION OUTPUT ;
    USE SIGNAL ;
    PORT
      LAYER met3 ;
        RECT 0.000 195.880 4.000 196.480 ;
    END
  END io_out[2]
  PIN io_out[30]
    DIRECTION OUTPUT ;
    USE SIGNAL ;
    ANTENNADIFFAREA 2.673000 ;
    PORT
      LAYER met3 ;
        RECT 0.000 310.120 4.000 310.720 ;
    END
  END io_out[30]
  PIN io_out[3]
    DIRECTION OUTPUT ;
    USE SIGNAL ;
    PORT
      LAYER met3 ;
        RECT 0.000 199.960 4.000 200.560 ;
    END
  END io_out[3]
  PIN io_out[4]
    DIRECTION OUTPUT ;
    USE SIGNAL ;
    PORT
      LAYER met3 ;
        RECT 0.000 204.040 4.000 204.640 ;
    END
  END io_out[4]
  PIN io_out[5]
    DIRECTION OUTPUT ;
    USE SIGNAL ;
    PORT
      LAYER met3 ;
        RECT 0.000 208.120 4.000 208.720 ;
    END
  END io_out[5]
  PIN io_out[6]
    DIRECTION OUTPUT ;
    USE SIGNAL ;
    PORT
      LAYER met3 ;
        RECT 0.000 212.200 4.000 212.800 ;
    END
  END io_out[6]
  PIN io_out[7]
    DIRECTION OUTPUT ;
    USE SIGNAL ;
    PORT
      LAYER met3 ;
        RECT 0.000 216.280 4.000 216.880 ;
    END
  END io_out[7]
  PIN io_out[8]
    DIRECTION OUTPUT ;
    USE SIGNAL ;
    PORT
      LAYER met3 ;
        RECT 0.000 220.360 4.000 220.960 ;
    END
  END io_out[8]
  PIN io_out[9]
    DIRECTION OUTPUT ;
    USE SIGNAL ;
    ANTENNADIFFAREA 2.673000 ;
    PORT
      LAYER met3 ;
        RECT 0.000 224.440 4.000 225.040 ;
    END
  END io_out[9]
  PIN sram_ack_i
    DIRECTION INPUT ;
    USE SIGNAL ;
    ANTENNAGATEAREA 0.213000 ;
    PORT
      LAYER met3 ;
        RECT 1196.000 262.520 1200.000 263.120 ;
    END
  END sram_ack_i
  PIN sram_adr_o[0]
    DIRECTION OUTPUT ;
    USE SIGNAL ;
    ANTENNADIFFAREA 2.673000 ;
    PORT
      LAYER met3 ;
        RECT 1196.000 267.960 1200.000 268.560 ;
    END
  END sram_adr_o[0]
  PIN sram_adr_o[10]
    DIRECTION OUTPUT ;
    USE SIGNAL ;
    ANTENNADIFFAREA 2.673000 ;
    PORT
      LAYER met3 ;
        RECT 1196.000 314.200 1200.000 314.800 ;
    END
  END sram_adr_o[10]
  PIN sram_adr_o[11]
    DIRECTION OUTPUT ;
    USE SIGNAL ;
    ANTENNADIFFAREA 2.673000 ;
    PORT
      LAYER met3 ;
        RECT 1196.000 318.280 1200.000 318.880 ;
    END
  END sram_adr_o[11]
  PIN sram_adr_o[12]
    DIRECTION OUTPUT ;
    USE SIGNAL ;
    ANTENNADIFFAREA 2.673000 ;
    PORT
      LAYER met3 ;
        RECT 1196.000 322.360 1200.000 322.960 ;
    END
  END sram_adr_o[12]
  PIN sram_adr_o[13]
    DIRECTION OUTPUT ;
    USE SIGNAL ;
    ANTENNADIFFAREA 2.673000 ;
    PORT
      LAYER met3 ;
        RECT 1196.000 326.440 1200.000 327.040 ;
    END
  END sram_adr_o[13]
  PIN sram_adr_o[14]
    DIRECTION OUTPUT ;
    USE SIGNAL ;
    ANTENNADIFFAREA 2.673000 ;
    PORT
      LAYER met3 ;
        RECT 1196.000 330.520 1200.000 331.120 ;
    END
  END sram_adr_o[14]
  PIN sram_adr_o[15]
    DIRECTION OUTPUT ;
    USE SIGNAL ;
    ANTENNADIFFAREA 2.673000 ;
    PORT
      LAYER met3 ;
        RECT 1196.000 334.600 1200.000 335.200 ;
    END
  END sram_adr_o[15]
  PIN sram_adr_o[16]
    DIRECTION OUTPUT ;
    USE SIGNAL ;
    ANTENNADIFFAREA 2.673000 ;
    PORT
      LAYER met3 ;
        RECT 1196.000 338.680 1200.000 339.280 ;
    END
  END sram_adr_o[16]
  PIN sram_adr_o[17]
    DIRECTION OUTPUT ;
    USE SIGNAL ;
    ANTENNADIFFAREA 2.673000 ;
    PORT
      LAYER met3 ;
        RECT 1196.000 342.760 1200.000 343.360 ;
    END
  END sram_adr_o[17]
  PIN sram_adr_o[18]
    DIRECTION OUTPUT ;
    USE SIGNAL ;
    ANTENNADIFFAREA 2.673000 ;
    PORT
      LAYER met3 ;
        RECT 1196.000 346.840 1200.000 347.440 ;
    END
  END sram_adr_o[18]
  PIN sram_adr_o[19]
    DIRECTION OUTPUT ;
    USE SIGNAL ;
    ANTENNADIFFAREA 2.673000 ;
    PORT
      LAYER met3 ;
        RECT 1196.000 350.920 1200.000 351.520 ;
    END
  END sram_adr_o[19]
  PIN sram_adr_o[1]
    DIRECTION OUTPUT ;
    USE SIGNAL ;
    ANTENNADIFFAREA 2.673000 ;
    PORT
      LAYER met3 ;
        RECT 1196.000 273.400 1200.000 274.000 ;
    END
  END sram_adr_o[1]
  PIN sram_adr_o[20]
    DIRECTION OUTPUT ;
    USE SIGNAL ;
    ANTENNADIFFAREA 2.673000 ;
    PORT
      LAYER met3 ;
        RECT 1196.000 355.000 1200.000 355.600 ;
    END
  END sram_adr_o[20]
  PIN sram_adr_o[21]
    DIRECTION OUTPUT ;
    USE SIGNAL ;
    ANTENNADIFFAREA 2.673000 ;
    PORT
      LAYER met3 ;
        RECT 1196.000 359.080 1200.000 359.680 ;
    END
  END sram_adr_o[21]
  PIN sram_adr_o[22]
    DIRECTION OUTPUT ;
    USE SIGNAL ;
    ANTENNADIFFAREA 2.673000 ;
    PORT
      LAYER met3 ;
        RECT 1196.000 363.160 1200.000 363.760 ;
    END
  END sram_adr_o[22]
  PIN sram_adr_o[23]
    DIRECTION OUTPUT ;
    USE SIGNAL ;
    ANTENNADIFFAREA 2.673000 ;
    PORT
      LAYER met3 ;
        RECT 1196.000 367.240 1200.000 367.840 ;
    END
  END sram_adr_o[23]
  PIN sram_adr_o[24]
    DIRECTION OUTPUT ;
    USE SIGNAL ;
    ANTENNADIFFAREA 2.673000 ;
    PORT
      LAYER met3 ;
        RECT 1196.000 371.320 1200.000 371.920 ;
    END
  END sram_adr_o[24]
  PIN sram_adr_o[25]
    DIRECTION OUTPUT ;
    USE SIGNAL ;
    ANTENNADIFFAREA 2.673000 ;
    PORT
      LAYER met3 ;
        RECT 1196.000 375.400 1200.000 376.000 ;
    END
  END sram_adr_o[25]
  PIN sram_adr_o[26]
    DIRECTION OUTPUT ;
    USE SIGNAL ;
    ANTENNADIFFAREA 2.673000 ;
    PORT
      LAYER met3 ;
        RECT 1196.000 379.480 1200.000 380.080 ;
    END
  END sram_adr_o[26]
  PIN sram_adr_o[27]
    DIRECTION OUTPUT ;
    USE SIGNAL ;
    ANTENNADIFFAREA 2.673000 ;
    PORT
      LAYER met3 ;
        RECT 1196.000 383.560 1200.000 384.160 ;
    END
  END sram_adr_o[27]
  PIN sram_adr_o[28]
    DIRECTION OUTPUT ;
    USE SIGNAL ;
    ANTENNADIFFAREA 2.673000 ;
    PORT
      LAYER met3 ;
        RECT 1196.000 387.640 1200.000 388.240 ;
    END
  END sram_adr_o[28]
  PIN sram_adr_o[29]
    DIRECTION OUTPUT ;
    USE SIGNAL ;
    ANTENNADIFFAREA 2.673000 ;
    PORT
      LAYER met3 ;
        RECT 1196.000 391.720 1200.000 392.320 ;
    END
  END sram_adr_o[29]
  PIN sram_adr_o[2]
    DIRECTION OUTPUT ;
    USE SIGNAL ;
    ANTENNADIFFAREA 2.673000 ;
    PORT
      LAYER met3 ;
        RECT 1196.000 278.840 1200.000 279.440 ;
    END
  END sram_adr_o[2]
  PIN sram_adr_o[30]
    DIRECTION OUTPUT ;
    USE SIGNAL ;
    ANTENNADIFFAREA 2.673000 ;
    PORT
      LAYER met3 ;
        RECT 1196.000 395.800 1200.000 396.400 ;
    END
  END sram_adr_o[30]
  PIN sram_adr_o[31]
    DIRECTION OUTPUT ;
    USE SIGNAL ;
    ANTENNADIFFAREA 2.673000 ;
    PORT
      LAYER met3 ;
        RECT 1196.000 399.880 1200.000 400.480 ;
    END
  END sram_adr_o[31]
  PIN sram_adr_o[3]
    DIRECTION OUTPUT ;
    USE SIGNAL ;
    ANTENNADIFFAREA 2.673000 ;
    PORT
      LAYER met3 ;
        RECT 1196.000 284.280 1200.000 284.880 ;
    END
  END sram_adr_o[3]
  PIN sram_adr_o[4]
    DIRECTION OUTPUT ;
    USE SIGNAL ;
    ANTENNADIFFAREA 2.673000 ;
    PORT
      LAYER met3 ;
        RECT 1196.000 289.720 1200.000 290.320 ;
    END
  END sram_adr_o[4]
  PIN sram_adr_o[5]
    DIRECTION OUTPUT ;
    USE SIGNAL ;
    ANTENNADIFFAREA 2.673000 ;
    PORT
      LAYER met3 ;
        RECT 1196.000 293.800 1200.000 294.400 ;
    END
  END sram_adr_o[5]
  PIN sram_adr_o[6]
    DIRECTION OUTPUT ;
    USE SIGNAL ;
    ANTENNADIFFAREA 2.673000 ;
    PORT
      LAYER met3 ;
        RECT 1196.000 297.880 1200.000 298.480 ;
    END
  END sram_adr_o[6]
  PIN sram_adr_o[7]
    DIRECTION OUTPUT ;
    USE SIGNAL ;
    ANTENNADIFFAREA 2.673000 ;
    PORT
      LAYER met3 ;
        RECT 1196.000 301.960 1200.000 302.560 ;
    END
  END sram_adr_o[7]
  PIN sram_adr_o[8]
    DIRECTION OUTPUT ;
    USE SIGNAL ;
    ANTENNADIFFAREA 2.673000 ;
    PORT
      LAYER met3 ;
        RECT 1196.000 306.040 1200.000 306.640 ;
    END
  END sram_adr_o[8]
  PIN sram_adr_o[9]
    DIRECTION OUTPUT ;
    USE SIGNAL ;
    ANTENNADIFFAREA 2.673000 ;
    PORT
      LAYER met3 ;
        RECT 1196.000 310.120 1200.000 310.720 ;
    END
  END sram_adr_o[9]
  PIN sram_cyc_o
    DIRECTION OUTPUT ;
    USE SIGNAL ;
    ANTENNADIFFAREA 2.673000 ;
    PORT
      LAYER met3 ;
        RECT 1196.000 263.880 1200.000 264.480 ;
    END
  END sram_cyc_o
  PIN sram_dat_i[0]
    DIRECTION INPUT ;
    USE SIGNAL ;
    ANTENNAGATEAREA 0.126000 ;
    PORT
      LAYER met3 ;
        RECT 1196.000 269.320 1200.000 269.920 ;
    END
  END sram_dat_i[0]
  PIN sram_dat_i[10]
    DIRECTION INPUT ;
    USE SIGNAL ;
    ANTENNAGATEAREA 0.126000 ;
    PORT
      LAYER met3 ;
        RECT 1196.000 315.560 1200.000 316.160 ;
    END
  END sram_dat_i[10]
  PIN sram_dat_i[11]
    DIRECTION INPUT ;
    USE SIGNAL ;
    ANTENNAGATEAREA 0.126000 ;
    PORT
      LAYER met3 ;
        RECT 1196.000 319.640 1200.000 320.240 ;
    END
  END sram_dat_i[11]
  PIN sram_dat_i[12]
    DIRECTION INPUT ;
    USE SIGNAL ;
    ANTENNAGATEAREA 0.126000 ;
    PORT
      LAYER met3 ;
        RECT 1196.000 323.720 1200.000 324.320 ;
    END
  END sram_dat_i[12]
  PIN sram_dat_i[13]
    DIRECTION INPUT ;
    USE SIGNAL ;
    ANTENNAGATEAREA 0.126000 ;
    PORT
      LAYER met3 ;
        RECT 1196.000 327.800 1200.000 328.400 ;
    END
  END sram_dat_i[13]
  PIN sram_dat_i[14]
    DIRECTION INPUT ;
    USE SIGNAL ;
    ANTENNAGATEAREA 0.126000 ;
    PORT
      LAYER met3 ;
        RECT 1196.000 331.880 1200.000 332.480 ;
    END
  END sram_dat_i[14]
  PIN sram_dat_i[15]
    DIRECTION INPUT ;
    USE SIGNAL ;
    ANTENNAGATEAREA 0.196500 ;
    PORT
      LAYER met3 ;
        RECT 1196.000 335.960 1200.000 336.560 ;
    END
  END sram_dat_i[15]
  PIN sram_dat_i[16]
    DIRECTION INPUT ;
    USE SIGNAL ;
    ANTENNAGATEAREA 0.196500 ;
    PORT
      LAYER met3 ;
        RECT 1196.000 340.040 1200.000 340.640 ;
    END
  END sram_dat_i[16]
  PIN sram_dat_i[17]
    DIRECTION INPUT ;
    USE SIGNAL ;
    ANTENNAGATEAREA 0.196500 ;
    PORT
      LAYER met3 ;
        RECT 1196.000 344.120 1200.000 344.720 ;
    END
  END sram_dat_i[17]
  PIN sram_dat_i[18]
    DIRECTION INPUT ;
    USE SIGNAL ;
    ANTENNAGATEAREA 0.196500 ;
    PORT
      LAYER met3 ;
        RECT 1196.000 348.200 1200.000 348.800 ;
    END
  END sram_dat_i[18]
  PIN sram_dat_i[19]
    DIRECTION INPUT ;
    USE SIGNAL ;
    ANTENNAGATEAREA 0.196500 ;
    PORT
      LAYER met3 ;
        RECT 1196.000 352.280 1200.000 352.880 ;
    END
  END sram_dat_i[19]
  PIN sram_dat_i[1]
    DIRECTION INPUT ;
    USE SIGNAL ;
    ANTENNAGATEAREA 0.196500 ;
    PORT
      LAYER met3 ;
        RECT 1196.000 274.760 1200.000 275.360 ;
    END
  END sram_dat_i[1]
  PIN sram_dat_i[20]
    DIRECTION INPUT ;
    USE SIGNAL ;
    ANTENNAGATEAREA 0.196500 ;
    PORT
      LAYER met3 ;
        RECT 1196.000 356.360 1200.000 356.960 ;
    END
  END sram_dat_i[20]
  PIN sram_dat_i[21]
    DIRECTION INPUT ;
    USE SIGNAL ;
    ANTENNAGATEAREA 0.196500 ;
    PORT
      LAYER met3 ;
        RECT 1196.000 360.440 1200.000 361.040 ;
    END
  END sram_dat_i[21]
  PIN sram_dat_i[22]
    DIRECTION INPUT ;
    USE SIGNAL ;
    ANTENNAGATEAREA 0.196500 ;
    PORT
      LAYER met3 ;
        RECT 1196.000 364.520 1200.000 365.120 ;
    END
  END sram_dat_i[22]
  PIN sram_dat_i[23]
    DIRECTION INPUT ;
    USE SIGNAL ;
    ANTENNAGATEAREA 0.196500 ;
    PORT
      LAYER met3 ;
        RECT 1196.000 368.600 1200.000 369.200 ;
    END
  END sram_dat_i[23]
  PIN sram_dat_i[24]
    DIRECTION INPUT ;
    USE SIGNAL ;
    ANTENNAGATEAREA 0.196500 ;
    PORT
      LAYER met3 ;
        RECT 1196.000 372.680 1200.000 373.280 ;
    END
  END sram_dat_i[24]
  PIN sram_dat_i[25]
    DIRECTION INPUT ;
    USE SIGNAL ;
    ANTENNAGATEAREA 0.196500 ;
    PORT
      LAYER met3 ;
        RECT 1196.000 376.760 1200.000 377.360 ;
    END
  END sram_dat_i[25]
  PIN sram_dat_i[26]
    DIRECTION INPUT ;
    USE SIGNAL ;
    ANTENNAGATEAREA 0.196500 ;
    PORT
      LAYER met3 ;
        RECT 1196.000 380.840 1200.000 381.440 ;
    END
  END sram_dat_i[26]
  PIN sram_dat_i[27]
    DIRECTION INPUT ;
    USE SIGNAL ;
    ANTENNAGATEAREA 0.196500 ;
    PORT
      LAYER met3 ;
        RECT 1196.000 384.920 1200.000 385.520 ;
    END
  END sram_dat_i[27]
  PIN sram_dat_i[28]
    DIRECTION INPUT ;
    USE SIGNAL ;
    ANTENNAGATEAREA 0.196500 ;
    PORT
      LAYER met3 ;
        RECT 1196.000 389.000 1200.000 389.600 ;
    END
  END sram_dat_i[28]
  PIN sram_dat_i[29]
    DIRECTION INPUT ;
    USE SIGNAL ;
    ANTENNAGATEAREA 0.196500 ;
    PORT
      LAYER met3 ;
        RECT 1196.000 393.080 1200.000 393.680 ;
    END
  END sram_dat_i[29]
  PIN sram_dat_i[2]
    DIRECTION INPUT ;
    USE SIGNAL ;
    ANTENNAGATEAREA 0.126000 ;
    PORT
      LAYER met3 ;
        RECT 1196.000 280.200 1200.000 280.800 ;
    END
  END sram_dat_i[2]
  PIN sram_dat_i[30]
    DIRECTION INPUT ;
    USE SIGNAL ;
    ANTENNAGATEAREA 0.196500 ;
    PORT
      LAYER met3 ;
        RECT 1196.000 397.160 1200.000 397.760 ;
    END
  END sram_dat_i[30]
  PIN sram_dat_i[31]
    DIRECTION INPUT ;
    USE SIGNAL ;
    ANTENNAGATEAREA 0.196500 ;
    PORT
      LAYER met3 ;
        RECT 1196.000 401.240 1200.000 401.840 ;
    END
  END sram_dat_i[31]
  PIN sram_dat_i[3]
    DIRECTION INPUT ;
    USE SIGNAL ;
    ANTENNAGATEAREA 0.126000 ;
    PORT
      LAYER met3 ;
        RECT 1196.000 285.640 1200.000 286.240 ;
    END
  END sram_dat_i[3]
  PIN sram_dat_i[4]
    DIRECTION INPUT ;
    USE SIGNAL ;
    ANTENNAGATEAREA 0.213000 ;
    PORT
      LAYER met3 ;
        RECT 1196.000 291.080 1200.000 291.680 ;
    END
  END sram_dat_i[4]
  PIN sram_dat_i[5]
    DIRECTION INPUT ;
    USE SIGNAL ;
    ANTENNAGATEAREA 0.126000 ;
    PORT
      LAYER met3 ;
        RECT 1196.000 295.160 1200.000 295.760 ;
    END
  END sram_dat_i[5]
  PIN sram_dat_i[6]
    DIRECTION INPUT ;
    USE SIGNAL ;
    ANTENNAGATEAREA 0.196500 ;
    PORT
      LAYER met3 ;
        RECT 1196.000 299.240 1200.000 299.840 ;
    END
  END sram_dat_i[6]
  PIN sram_dat_i[7]
    DIRECTION INPUT ;
    USE SIGNAL ;
    ANTENNAGATEAREA 0.196500 ;
    PORT
      LAYER met3 ;
        RECT 1196.000 303.320 1200.000 303.920 ;
    END
  END sram_dat_i[7]
  PIN sram_dat_i[8]
    DIRECTION INPUT ;
    USE SIGNAL ;
    ANTENNAGATEAREA 0.196500 ;
    PORT
      LAYER met3 ;
        RECT 1196.000 307.400 1200.000 308.000 ;
    END
  END sram_dat_i[8]
  PIN sram_dat_i[9]
    DIRECTION INPUT ;
    USE SIGNAL ;
    ANTENNAGATEAREA 0.196500 ;
    PORT
      LAYER met3 ;
        RECT 1196.000 311.480 1200.000 312.080 ;
    END
  END sram_dat_i[9]
  PIN sram_dat_o[0]
    DIRECTION OUTPUT ;
    USE SIGNAL ;
    ANTENNADIFFAREA 2.673000 ;
    PORT
      LAYER met3 ;
        RECT 1196.000 270.680 1200.000 271.280 ;
    END
  END sram_dat_o[0]
  PIN sram_dat_o[10]
    DIRECTION OUTPUT ;
    USE SIGNAL ;
    ANTENNADIFFAREA 2.673000 ;
    PORT
      LAYER met3 ;
        RECT 1196.000 316.920 1200.000 317.520 ;
    END
  END sram_dat_o[10]
  PIN sram_dat_o[11]
    DIRECTION OUTPUT ;
    USE SIGNAL ;
    ANTENNADIFFAREA 2.673000 ;
    PORT
      LAYER met3 ;
        RECT 1196.000 321.000 1200.000 321.600 ;
    END
  END sram_dat_o[11]
  PIN sram_dat_o[12]
    DIRECTION OUTPUT ;
    USE SIGNAL ;
    ANTENNADIFFAREA 2.673000 ;
    PORT
      LAYER met3 ;
        RECT 1196.000 325.080 1200.000 325.680 ;
    END
  END sram_dat_o[12]
  PIN sram_dat_o[13]
    DIRECTION OUTPUT ;
    USE SIGNAL ;
    ANTENNADIFFAREA 2.673000 ;
    PORT
      LAYER met3 ;
        RECT 1196.000 329.160 1200.000 329.760 ;
    END
  END sram_dat_o[13]
  PIN sram_dat_o[14]
    DIRECTION OUTPUT ;
    USE SIGNAL ;
    ANTENNADIFFAREA 2.673000 ;
    PORT
      LAYER met3 ;
        RECT 1196.000 333.240 1200.000 333.840 ;
    END
  END sram_dat_o[14]
  PIN sram_dat_o[15]
    DIRECTION OUTPUT ;
    USE SIGNAL ;
    ANTENNADIFFAREA 2.673000 ;
    PORT
      LAYER met3 ;
        RECT 1196.000 337.320 1200.000 337.920 ;
    END
  END sram_dat_o[15]
  PIN sram_dat_o[16]
    DIRECTION OUTPUT ;
    USE SIGNAL ;
    ANTENNADIFFAREA 2.673000 ;
    PORT
      LAYER met3 ;
        RECT 1196.000 341.400 1200.000 342.000 ;
    END
  END sram_dat_o[16]
  PIN sram_dat_o[17]
    DIRECTION OUTPUT ;
    USE SIGNAL ;
    ANTENNADIFFAREA 2.673000 ;
    PORT
      LAYER met3 ;
        RECT 1196.000 345.480 1200.000 346.080 ;
    END
  END sram_dat_o[17]
  PIN sram_dat_o[18]
    DIRECTION OUTPUT ;
    USE SIGNAL ;
    ANTENNADIFFAREA 2.673000 ;
    PORT
      LAYER met3 ;
        RECT 1196.000 349.560 1200.000 350.160 ;
    END
  END sram_dat_o[18]
  PIN sram_dat_o[19]
    DIRECTION OUTPUT ;
    USE SIGNAL ;
    ANTENNADIFFAREA 2.673000 ;
    PORT
      LAYER met3 ;
        RECT 1196.000 353.640 1200.000 354.240 ;
    END
  END sram_dat_o[19]
  PIN sram_dat_o[1]
    DIRECTION OUTPUT ;
    USE SIGNAL ;
    ANTENNADIFFAREA 2.673000 ;
    PORT
      LAYER met3 ;
        RECT 1196.000 276.120 1200.000 276.720 ;
    END
  END sram_dat_o[1]
  PIN sram_dat_o[20]
    DIRECTION OUTPUT ;
    USE SIGNAL ;
    ANTENNADIFFAREA 2.673000 ;
    PORT
      LAYER met3 ;
        RECT 1196.000 357.720 1200.000 358.320 ;
    END
  END sram_dat_o[20]
  PIN sram_dat_o[21]
    DIRECTION OUTPUT ;
    USE SIGNAL ;
    ANTENNADIFFAREA 2.673000 ;
    PORT
      LAYER met3 ;
        RECT 1196.000 361.800 1200.000 362.400 ;
    END
  END sram_dat_o[21]
  PIN sram_dat_o[22]
    DIRECTION OUTPUT ;
    USE SIGNAL ;
    ANTENNADIFFAREA 2.673000 ;
    PORT
      LAYER met3 ;
        RECT 1196.000 365.880 1200.000 366.480 ;
    END
  END sram_dat_o[22]
  PIN sram_dat_o[23]
    DIRECTION OUTPUT ;
    USE SIGNAL ;
    ANTENNADIFFAREA 2.673000 ;
    PORT
      LAYER met3 ;
        RECT 1196.000 369.960 1200.000 370.560 ;
    END
  END sram_dat_o[23]
  PIN sram_dat_o[24]
    DIRECTION OUTPUT ;
    USE SIGNAL ;
    ANTENNADIFFAREA 2.673000 ;
    PORT
      LAYER met3 ;
        RECT 1196.000 374.040 1200.000 374.640 ;
    END
  END sram_dat_o[24]
  PIN sram_dat_o[25]
    DIRECTION OUTPUT ;
    USE SIGNAL ;
    ANTENNADIFFAREA 2.673000 ;
    PORT
      LAYER met3 ;
        RECT 1196.000 378.120 1200.000 378.720 ;
    END
  END sram_dat_o[25]
  PIN sram_dat_o[26]
    DIRECTION OUTPUT ;
    USE SIGNAL ;
    ANTENNADIFFAREA 2.673000 ;
    PORT
      LAYER met3 ;
        RECT 1196.000 382.200 1200.000 382.800 ;
    END
  END sram_dat_o[26]
  PIN sram_dat_o[27]
    DIRECTION OUTPUT ;
    USE SIGNAL ;
    ANTENNADIFFAREA 2.673000 ;
    PORT
      LAYER met3 ;
        RECT 1196.000 386.280 1200.000 386.880 ;
    END
  END sram_dat_o[27]
  PIN sram_dat_o[28]
    DIRECTION OUTPUT ;
    USE SIGNAL ;
    ANTENNADIFFAREA 2.673000 ;
    PORT
      LAYER met3 ;
        RECT 1196.000 390.360 1200.000 390.960 ;
    END
  END sram_dat_o[28]
  PIN sram_dat_o[29]
    DIRECTION OUTPUT ;
    USE SIGNAL ;
    ANTENNADIFFAREA 2.673000 ;
    PORT
      LAYER met3 ;
        RECT 1196.000 394.440 1200.000 395.040 ;
    END
  END sram_dat_o[29]
  PIN sram_dat_o[2]
    DIRECTION OUTPUT ;
    USE SIGNAL ;
    ANTENNADIFFAREA 2.673000 ;
    PORT
      LAYER met3 ;
        RECT 1196.000 281.560 1200.000 282.160 ;
    END
  END sram_dat_o[2]
  PIN sram_dat_o[30]
    DIRECTION OUTPUT ;
    USE SIGNAL ;
    ANTENNADIFFAREA 2.673000 ;
    PORT
      LAYER met3 ;
        RECT 1196.000 398.520 1200.000 399.120 ;
    END
  END sram_dat_o[30]
  PIN sram_dat_o[31]
    DIRECTION OUTPUT ;
    USE SIGNAL ;
    ANTENNADIFFAREA 2.673000 ;
    PORT
      LAYER met3 ;
        RECT 1196.000 402.600 1200.000 403.200 ;
    END
  END sram_dat_o[31]
  PIN sram_dat_o[3]
    DIRECTION OUTPUT ;
    USE SIGNAL ;
    ANTENNADIFFAREA 2.673000 ;
    PORT
      LAYER met3 ;
        RECT 1196.000 287.000 1200.000 287.600 ;
    END
  END sram_dat_o[3]
  PIN sram_dat_o[4]
    DIRECTION OUTPUT ;
    USE SIGNAL ;
    ANTENNADIFFAREA 2.673000 ;
    PORT
      LAYER met3 ;
        RECT 1196.000 292.440 1200.000 293.040 ;
    END
  END sram_dat_o[4]
  PIN sram_dat_o[5]
    DIRECTION OUTPUT ;
    USE SIGNAL ;
    ANTENNADIFFAREA 2.673000 ;
    PORT
      LAYER met3 ;
        RECT 1196.000 296.520 1200.000 297.120 ;
    END
  END sram_dat_o[5]
  PIN sram_dat_o[6]
    DIRECTION OUTPUT ;
    USE SIGNAL ;
    ANTENNADIFFAREA 2.673000 ;
    PORT
      LAYER met3 ;
        RECT 1196.000 300.600 1200.000 301.200 ;
    END
  END sram_dat_o[6]
  PIN sram_dat_o[7]
    DIRECTION OUTPUT ;
    USE SIGNAL ;
    ANTENNADIFFAREA 2.673000 ;
    PORT
      LAYER met3 ;
        RECT 1196.000 304.680 1200.000 305.280 ;
    END
  END sram_dat_o[7]
  PIN sram_dat_o[8]
    DIRECTION OUTPUT ;
    USE SIGNAL ;
    ANTENNADIFFAREA 2.673000 ;
    PORT
      LAYER met3 ;
        RECT 1196.000 308.760 1200.000 309.360 ;
    END
  END sram_dat_o[8]
  PIN sram_dat_o[9]
    DIRECTION OUTPUT ;
    USE SIGNAL ;
    ANTENNADIFFAREA 2.673000 ;
    PORT
      LAYER met3 ;
        RECT 1196.000 312.840 1200.000 313.440 ;
    END
  END sram_dat_o[9]
  PIN sram_sel_o[0]
    DIRECTION OUTPUT ;
    USE SIGNAL ;
    PORT
      LAYER met3 ;
        RECT 1196.000 272.040 1200.000 272.640 ;
    END
  END sram_sel_o[0]
  PIN sram_sel_o[1]
    DIRECTION OUTPUT ;
    USE SIGNAL ;
    PORT
      LAYER met3 ;
        RECT 1196.000 277.480 1200.000 278.080 ;
    END
  END sram_sel_o[1]
  PIN sram_sel_o[2]
    DIRECTION OUTPUT ;
    USE SIGNAL ;
    PORT
      LAYER met3 ;
        RECT 1196.000 282.920 1200.000 283.520 ;
    END
  END sram_sel_o[2]
  PIN sram_sel_o[3]
    DIRECTION OUTPUT ;
    USE SIGNAL ;
    PORT
      LAYER met3 ;
        RECT 1196.000 288.360 1200.000 288.960 ;
    END
  END sram_sel_o[3]
  PIN sram_stb_o
    DIRECTION OUTPUT ;
    USE SIGNAL ;
    ANTENNADIFFAREA 2.673000 ;
    PORT
      LAYER met3 ;
        RECT 1196.000 265.240 1200.000 265.840 ;
    END
  END sram_stb_o
  PIN sram_we_o
    DIRECTION OUTPUT ;
    USE SIGNAL ;
    ANTENNADIFFAREA 2.673000 ;
    PORT
      LAYER met3 ;
        RECT 1196.000 266.600 1200.000 267.200 ;
    END
  END sram_we_o
  PIN user_irq[0]
    DIRECTION OUTPUT ;
    USE SIGNAL ;
    ANTENNADIFFAREA 2.673000 ;
    PORT
      LAYER met2 ;
        RECT 1012.090 0.000 1012.370 4.000 ;
    END
  END user_irq[0]
  PIN user_irq[1]
    DIRECTION OUTPUT ;
    USE SIGNAL ;
    ANTENNADIFFAREA 2.673000 ;
    PORT
      LAYER met2 ;
        RECT 1087.070 0.000 1087.350 4.000 ;
    END
  END user_irq[1]
  PIN user_irq[2]
    DIRECTION OUTPUT ;
    USE SIGNAL ;
    ANTENNADIFFAREA 2.673000 ;
    PORT
      LAYER met2 ;
        RECT 1162.050 0.000 1162.330 4.000 ;
    END
  END user_irq[2]
  PIN vccd1
    DIRECTION INOUT ;
    USE POWER ;
    PORT
      LAYER met4 ;
        RECT 21.040 10.640 22.640 487.120 ;
    END
    PORT
      LAYER met4 ;
        RECT 174.640 10.640 176.240 487.120 ;
    END
    PORT
      LAYER met4 ;
        RECT 328.240 10.640 329.840 487.120 ;
    END
    PORT
      LAYER met4 ;
        RECT 481.840 10.640 483.440 487.120 ;
    END
    PORT
      LAYER met4 ;
        RECT 635.440 10.640 637.040 487.120 ;
    END
    PORT
      LAYER met4 ;
        RECT 789.040 10.640 790.640 487.120 ;
    END
    PORT
      LAYER met4 ;
        RECT 942.640 10.640 944.240 487.120 ;
    END
    PORT
      LAYER met4 ;
        RECT 1096.240 10.640 1097.840 487.120 ;
    END
  END vccd1
  PIN vssd1
    DIRECTION INOUT ;
    USE GROUND ;
    PORT
      LAYER met4 ;
        RECT 24.340 10.640 25.940 487.120 ;
    END
    PORT
      LAYER met4 ;
        RECT 177.940 10.640 179.540 487.120 ;
    END
    PORT
      LAYER met4 ;
        RECT 331.540 10.640 333.140 487.120 ;
    END
    PORT
      LAYER met4 ;
        RECT 485.140 10.640 486.740 487.120 ;
    END
    PORT
      LAYER met4 ;
        RECT 638.740 10.640 640.340 487.120 ;
    END
    PORT
      LAYER met4 ;
        RECT 792.340 10.640 793.940 487.120 ;
    END
    PORT
      LAYER met4 ;
        RECT 945.940 10.640 947.540 487.120 ;
    END
    PORT
      LAYER met4 ;
        RECT 1099.540 10.640 1101.140 487.120 ;
    END
  END vssd1
  PIN wb_clk_i
    DIRECTION INPUT ;
    USE SIGNAL ;
    ANTENNAGATEAREA 0.852000 ;
    PORT
      LAYER met2 ;
        RECT 20.330 496.000 20.610 500.000 ;
    END
  END wb_clk_i
  PIN wb_rst_i
    DIRECTION INPUT ;
    USE SIGNAL ;
    ANTENNAGATEAREA 0.213000 ;
    PORT
      LAYER met2 ;
        RECT 31.370 496.000 31.650 500.000 ;
    END
  END wb_rst_i
  PIN wbs_ack_o
    DIRECTION OUTPUT ;
    USE SIGNAL ;
    ANTENNADIFFAREA 2.673000 ;
    PORT
      LAYER met2 ;
        RECT 42.410 496.000 42.690 500.000 ;
    END
  END wbs_ack_o
  PIN wbs_adr_i[0]
    DIRECTION INPUT ;
    USE SIGNAL ;
    ANTENNAGATEAREA 0.742500 ;
    PORT
      LAYER met2 ;
        RECT 86.570 496.000 86.850 500.000 ;
    END
  END wbs_adr_i[0]
  PIN wbs_adr_i[10]
    DIRECTION INPUT ;
    USE SIGNAL ;
    ANTENNAGATEAREA 0.247500 ;
    PORT
      LAYER met2 ;
        RECT 461.930 496.000 462.210 500.000 ;
    END
  END wbs_adr_i[10]
  PIN wbs_adr_i[11]
    DIRECTION INPUT ;
    USE SIGNAL ;
    ANTENNAGATEAREA 0.247500 ;
    PORT
      LAYER met2 ;
        RECT 495.050 496.000 495.330 500.000 ;
    END
  END wbs_adr_i[11]
  PIN wbs_adr_i[12]
    DIRECTION INPUT ;
    USE SIGNAL ;
    ANTENNAGATEAREA 0.126000 ;
    PORT
      LAYER met2 ;
        RECT 528.170 496.000 528.450 500.000 ;
    END
  END wbs_adr_i[12]
  PIN wbs_adr_i[13]
    DIRECTION INPUT ;
    USE SIGNAL ;
    ANTENNAGATEAREA 0.126000 ;
    PORT
      LAYER met2 ;
        RECT 561.290 496.000 561.570 500.000 ;
    END
  END wbs_adr_i[13]
  PIN wbs_adr_i[14]
    DIRECTION INPUT ;
    USE SIGNAL ;
    ANTENNAGATEAREA 0.126000 ;
    PORT
      LAYER met2 ;
        RECT 594.410 496.000 594.690 500.000 ;
    END
  END wbs_adr_i[14]
  PIN wbs_adr_i[15]
    DIRECTION INPUT ;
    USE SIGNAL ;
    ANTENNAGATEAREA 0.126000 ;
    PORT
      LAYER met2 ;
        RECT 627.530 496.000 627.810 500.000 ;
    END
  END wbs_adr_i[15]
  PIN wbs_adr_i[16]
    DIRECTION INPUT ;
    USE SIGNAL ;
    ANTENNAGATEAREA 0.126000 ;
    PORT
      LAYER met2 ;
        RECT 660.650 496.000 660.930 500.000 ;
    END
  END wbs_adr_i[16]
  PIN wbs_adr_i[17]
    DIRECTION INPUT ;
    USE SIGNAL ;
    ANTENNAGATEAREA 0.247500 ;
    PORT
      LAYER met2 ;
        RECT 693.770 496.000 694.050 500.000 ;
    END
  END wbs_adr_i[17]
  PIN wbs_adr_i[18]
    DIRECTION INPUT ;
    USE SIGNAL ;
    ANTENNAGATEAREA 0.247500 ;
    PORT
      LAYER met2 ;
        RECT 726.890 496.000 727.170 500.000 ;
    END
  END wbs_adr_i[18]
  PIN wbs_adr_i[19]
    DIRECTION INPUT ;
    USE SIGNAL ;
    ANTENNAGATEAREA 0.126000 ;
    PORT
      LAYER met2 ;
        RECT 760.010 496.000 760.290 500.000 ;
    END
  END wbs_adr_i[19]
  PIN wbs_adr_i[1]
    DIRECTION INPUT ;
    USE SIGNAL ;
    ANTENNAGATEAREA 0.126000 ;
    PORT
      LAYER met2 ;
        RECT 130.730 496.000 131.010 500.000 ;
    END
  END wbs_adr_i[1]
  PIN wbs_adr_i[20]
    DIRECTION INPUT ;
    USE SIGNAL ;
    ANTENNAGATEAREA 0.213000 ;
    PORT
      LAYER met2 ;
        RECT 793.130 496.000 793.410 500.000 ;
    END
  END wbs_adr_i[20]
  PIN wbs_adr_i[21]
    DIRECTION INPUT ;
    USE SIGNAL ;
    ANTENNAGATEAREA 0.213000 ;
    PORT
      LAYER met2 ;
        RECT 826.250 496.000 826.530 500.000 ;
    END
  END wbs_adr_i[21]
  PIN wbs_adr_i[22]
    DIRECTION INPUT ;
    USE SIGNAL ;
    ANTENNAGATEAREA 0.213000 ;
    PORT
      LAYER met2 ;
        RECT 859.370 496.000 859.650 500.000 ;
    END
  END wbs_adr_i[22]
  PIN wbs_adr_i[23]
    DIRECTION INPUT ;
    USE SIGNAL ;
    ANTENNAGATEAREA 0.126000 ;
    PORT
      LAYER met2 ;
        RECT 892.490 496.000 892.770 500.000 ;
    END
  END wbs_adr_i[23]
  PIN wbs_adr_i[24]
    DIRECTION INPUT ;
    USE SIGNAL ;
    ANTENNAGATEAREA 0.159000 ;
    PORT
      LAYER met2 ;
        RECT 925.610 496.000 925.890 500.000 ;
    END
  END wbs_adr_i[24]
  PIN wbs_adr_i[25]
    DIRECTION INPUT ;
    USE SIGNAL ;
    ANTENNAGATEAREA 0.159000 ;
    PORT
      LAYER met2 ;
        RECT 958.730 496.000 959.010 500.000 ;
    END
  END wbs_adr_i[25]
  PIN wbs_adr_i[26]
    DIRECTION INPUT ;
    USE SIGNAL ;
    ANTENNAGATEAREA 0.159000 ;
    PORT
      LAYER met2 ;
        RECT 991.850 496.000 992.130 500.000 ;
    END
  END wbs_adr_i[26]
  PIN wbs_adr_i[27]
    DIRECTION INPUT ;
    USE SIGNAL ;
    ANTENNAGATEAREA 0.126000 ;
    PORT
      LAYER met2 ;
        RECT 1024.970 496.000 1025.250 500.000 ;
    END
  END wbs_adr_i[27]
  PIN wbs_adr_i[28]
    DIRECTION INPUT ;
    USE SIGNAL ;
    ANTENNAGATEAREA 0.126000 ;
    PORT
      LAYER met2 ;
        RECT 1058.090 496.000 1058.370 500.000 ;
    END
  END wbs_adr_i[28]
  PIN wbs_adr_i[29]
    DIRECTION INPUT ;
    USE SIGNAL ;
    ANTENNAGATEAREA 0.196500 ;
    PORT
      LAYER met2 ;
        RECT 1091.210 496.000 1091.490 500.000 ;
    END
  END wbs_adr_i[29]
  PIN wbs_adr_i[2]
    DIRECTION INPUT ;
    USE SIGNAL ;
    ANTENNAGATEAREA 0.126000 ;
    PORT
      LAYER met2 ;
        RECT 174.890 496.000 175.170 500.000 ;
    END
  END wbs_adr_i[2]
  PIN wbs_adr_i[30]
    DIRECTION INPUT ;
    USE SIGNAL ;
    ANTENNAGATEAREA 0.126000 ;
    PORT
      LAYER met2 ;
        RECT 1124.330 496.000 1124.610 500.000 ;
    END
  END wbs_adr_i[30]
  PIN wbs_adr_i[31]
    DIRECTION INPUT ;
    USE SIGNAL ;
    ANTENNAGATEAREA 0.196500 ;
    PORT
      LAYER met2 ;
        RECT 1157.450 496.000 1157.730 500.000 ;
    END
  END wbs_adr_i[31]
  PIN wbs_adr_i[3]
    DIRECTION INPUT ;
    USE SIGNAL ;
    ANTENNAGATEAREA 0.126000 ;
    PORT
      LAYER met2 ;
        RECT 219.050 496.000 219.330 500.000 ;
    END
  END wbs_adr_i[3]
  PIN wbs_adr_i[4]
    DIRECTION INPUT ;
    USE SIGNAL ;
    ANTENNAGATEAREA 0.126000 ;
    PORT
      LAYER met2 ;
        RECT 263.210 496.000 263.490 500.000 ;
    END
  END wbs_adr_i[4]
  PIN wbs_adr_i[5]
    DIRECTION INPUT ;
    USE SIGNAL ;
    ANTENNAGATEAREA 0.126000 ;
    PORT
      LAYER met2 ;
        RECT 296.330 496.000 296.610 500.000 ;
    END
  END wbs_adr_i[5]
  PIN wbs_adr_i[6]
    DIRECTION INPUT ;
    USE SIGNAL ;
    ANTENNAGATEAREA 0.426000 ;
    PORT
      LAYER met2 ;
        RECT 329.450 496.000 329.730 500.000 ;
    END
  END wbs_adr_i[6]
  PIN wbs_adr_i[7]
    DIRECTION INPUT ;
    USE SIGNAL ;
    ANTENNAGATEAREA 0.426000 ;
    PORT
      LAYER met2 ;
        RECT 362.570 496.000 362.850 500.000 ;
    END
  END wbs_adr_i[7]
  PIN wbs_adr_i[8]
    DIRECTION INPUT ;
    USE SIGNAL ;
    ANTENNAGATEAREA 0.426000 ;
    PORT
      LAYER met2 ;
        RECT 395.690 496.000 395.970 500.000 ;
    END
  END wbs_adr_i[8]
  PIN wbs_adr_i[9]
    DIRECTION INPUT ;
    USE SIGNAL ;
    ANTENNAGATEAREA 0.247500 ;
    PORT
      LAYER met2 ;
        RECT 428.810 496.000 429.090 500.000 ;
    END
  END wbs_adr_i[9]
  PIN wbs_cyc_i
    DIRECTION INPUT ;
    USE SIGNAL ;
    ANTENNAGATEAREA 0.126000 ;
    PORT
      LAYER met2 ;
        RECT 53.450 496.000 53.730 500.000 ;
    END
  END wbs_cyc_i
  PIN wbs_dat_i[0]
    DIRECTION INPUT ;
    USE SIGNAL ;
    ANTENNAGATEAREA 0.126000 ;
    PORT
      LAYER met2 ;
        RECT 97.610 496.000 97.890 500.000 ;
    END
  END wbs_dat_i[0]
  PIN wbs_dat_i[10]
    DIRECTION INPUT ;
    USE SIGNAL ;
    ANTENNAGATEAREA 0.126000 ;
    PORT
      LAYER met2 ;
        RECT 472.970 496.000 473.250 500.000 ;
    END
  END wbs_dat_i[10]
  PIN wbs_dat_i[11]
    DIRECTION INPUT ;
    USE SIGNAL ;
    ANTENNAGATEAREA 0.126000 ;
    PORT
      LAYER met2 ;
        RECT 506.090 496.000 506.370 500.000 ;
    END
  END wbs_dat_i[11]
  PIN wbs_dat_i[12]
    DIRECTION INPUT ;
    USE SIGNAL ;
    ANTENNAGATEAREA 0.126000 ;
    PORT
      LAYER met2 ;
        RECT 539.210 496.000 539.490 500.000 ;
    END
  END wbs_dat_i[12]
  PIN wbs_dat_i[13]
    DIRECTION INPUT ;
    USE SIGNAL ;
    ANTENNAGATEAREA 0.126000 ;
    PORT
      LAYER met2 ;
        RECT 572.330 496.000 572.610 500.000 ;
    END
  END wbs_dat_i[13]
  PIN wbs_dat_i[14]
    DIRECTION INPUT ;
    USE SIGNAL ;
    ANTENNAGATEAREA 0.126000 ;
    PORT
      LAYER met2 ;
        RECT 605.450 496.000 605.730 500.000 ;
    END
  END wbs_dat_i[14]
  PIN wbs_dat_i[15]
    DIRECTION INPUT ;
    USE SIGNAL ;
    ANTENNAGATEAREA 0.126000 ;
    PORT
      LAYER met2 ;
        RECT 638.570 496.000 638.850 500.000 ;
    END
  END wbs_dat_i[15]
  PIN wbs_dat_i[16]
    DIRECTION INPUT ;
    USE SIGNAL ;
    ANTENNAGATEAREA 0.126000 ;
    PORT
      LAYER met2 ;
        RECT 671.690 496.000 671.970 500.000 ;
    END
  END wbs_dat_i[16]
  PIN wbs_dat_i[17]
    DIRECTION INPUT ;
    USE SIGNAL ;
    ANTENNAGATEAREA 0.126000 ;
    PORT
      LAYER met2 ;
        RECT 704.810 496.000 705.090 500.000 ;
    END
  END wbs_dat_i[17]
  PIN wbs_dat_i[18]
    DIRECTION INPUT ;
    USE SIGNAL ;
    ANTENNAGATEAREA 0.126000 ;
    PORT
      LAYER met2 ;
        RECT 737.930 496.000 738.210 500.000 ;
    END
  END wbs_dat_i[18]
  PIN wbs_dat_i[19]
    DIRECTION INPUT ;
    USE SIGNAL ;
    ANTENNAGATEAREA 0.126000 ;
    PORT
      LAYER met2 ;
        RECT 771.050 496.000 771.330 500.000 ;
    END
  END wbs_dat_i[19]
  PIN wbs_dat_i[1]
    DIRECTION INPUT ;
    USE SIGNAL ;
    ANTENNAGATEAREA 0.126000 ;
    PORT
      LAYER met2 ;
        RECT 141.770 496.000 142.050 500.000 ;
    END
  END wbs_dat_i[1]
  PIN wbs_dat_i[20]
    DIRECTION INPUT ;
    USE SIGNAL ;
    ANTENNAGATEAREA 0.126000 ;
    PORT
      LAYER met2 ;
        RECT 804.170 496.000 804.450 500.000 ;
    END
  END wbs_dat_i[20]
  PIN wbs_dat_i[21]
    DIRECTION INPUT ;
    USE SIGNAL ;
    ANTENNAGATEAREA 0.126000 ;
    PORT
      LAYER met2 ;
        RECT 837.290 496.000 837.570 500.000 ;
    END
  END wbs_dat_i[21]
  PIN wbs_dat_i[22]
    DIRECTION INPUT ;
    USE SIGNAL ;
    ANTENNAGATEAREA 0.126000 ;
    PORT
      LAYER met2 ;
        RECT 870.410 496.000 870.690 500.000 ;
    END
  END wbs_dat_i[22]
  PIN wbs_dat_i[23]
    DIRECTION INPUT ;
    USE SIGNAL ;
    ANTENNAGATEAREA 0.126000 ;
    PORT
      LAYER met2 ;
        RECT 903.530 496.000 903.810 500.000 ;
    END
  END wbs_dat_i[23]
  PIN wbs_dat_i[24]
    DIRECTION INPUT ;
    USE SIGNAL ;
    ANTENNAGATEAREA 0.126000 ;
    PORT
      LAYER met2 ;
        RECT 936.650 496.000 936.930 500.000 ;
    END
  END wbs_dat_i[24]
  PIN wbs_dat_i[25]
    DIRECTION INPUT ;
    USE SIGNAL ;
    ANTENNAGATEAREA 0.126000 ;
    PORT
      LAYER met2 ;
        RECT 969.770 496.000 970.050 500.000 ;
    END
  END wbs_dat_i[25]
  PIN wbs_dat_i[26]
    DIRECTION INPUT ;
    USE SIGNAL ;
    ANTENNAGATEAREA 0.126000 ;
    PORT
      LAYER met2 ;
        RECT 1002.890 496.000 1003.170 500.000 ;
    END
  END wbs_dat_i[26]
  PIN wbs_dat_i[27]
    DIRECTION INPUT ;
    USE SIGNAL ;
    ANTENNAGATEAREA 0.126000 ;
    PORT
      LAYER met2 ;
        RECT 1036.010 496.000 1036.290 500.000 ;
    END
  END wbs_dat_i[27]
  PIN wbs_dat_i[28]
    DIRECTION INPUT ;
    USE SIGNAL ;
    ANTENNAGATEAREA 0.126000 ;
    PORT
      LAYER met2 ;
        RECT 1069.130 496.000 1069.410 500.000 ;
    END
  END wbs_dat_i[28]
  PIN wbs_dat_i[29]
    DIRECTION INPUT ;
    USE SIGNAL ;
    ANTENNAGATEAREA 0.126000 ;
    PORT
      LAYER met2 ;
        RECT 1102.250 496.000 1102.530 500.000 ;
    END
  END wbs_dat_i[29]
  PIN wbs_dat_i[2]
    DIRECTION INPUT ;
    USE SIGNAL ;
    ANTENNAGATEAREA 0.126000 ;
    PORT
      LAYER met2 ;
        RECT 185.930 496.000 186.210 500.000 ;
    END
  END wbs_dat_i[2]
  PIN wbs_dat_i[30]
    DIRECTION INPUT ;
    USE SIGNAL ;
    ANTENNAGATEAREA 0.126000 ;
    PORT
      LAYER met2 ;
        RECT 1135.370 496.000 1135.650 500.000 ;
    END
  END wbs_dat_i[30]
  PIN wbs_dat_i[31]
    DIRECTION INPUT ;
    USE SIGNAL ;
    ANTENNAGATEAREA 0.126000 ;
    PORT
      LAYER met2 ;
        RECT 1168.490 496.000 1168.770 500.000 ;
    END
  END wbs_dat_i[31]
  PIN wbs_dat_i[3]
    DIRECTION INPUT ;
    USE SIGNAL ;
    ANTENNAGATEAREA 0.126000 ;
    PORT
      LAYER met2 ;
        RECT 230.090 496.000 230.370 500.000 ;
    END
  END wbs_dat_i[3]
  PIN wbs_dat_i[4]
    DIRECTION INPUT ;
    USE SIGNAL ;
    ANTENNAGATEAREA 0.126000 ;
    PORT
      LAYER met2 ;
        RECT 274.250 496.000 274.530 500.000 ;
    END
  END wbs_dat_i[4]
  PIN wbs_dat_i[5]
    DIRECTION INPUT ;
    USE SIGNAL ;
    ANTENNAGATEAREA 0.126000 ;
    PORT
      LAYER met2 ;
        RECT 307.370 496.000 307.650 500.000 ;
    END
  END wbs_dat_i[5]
  PIN wbs_dat_i[6]
    DIRECTION INPUT ;
    USE SIGNAL ;
    ANTENNAGATEAREA 0.126000 ;
    PORT
      LAYER met2 ;
        RECT 340.490 496.000 340.770 500.000 ;
    END
  END wbs_dat_i[6]
  PIN wbs_dat_i[7]
    DIRECTION INPUT ;
    USE SIGNAL ;
    ANTENNAGATEAREA 0.126000 ;
    PORT
      LAYER met2 ;
        RECT 373.610 496.000 373.890 500.000 ;
    END
  END wbs_dat_i[7]
  PIN wbs_dat_i[8]
    DIRECTION INPUT ;
    USE SIGNAL ;
    ANTENNAGATEAREA 0.126000 ;
    PORT
      LAYER met2 ;
        RECT 406.730 496.000 407.010 500.000 ;
    END
  END wbs_dat_i[8]
  PIN wbs_dat_i[9]
    DIRECTION INPUT ;
    USE SIGNAL ;
    ANTENNAGATEAREA 0.126000 ;
    PORT
      LAYER met2 ;
        RECT 439.850 496.000 440.130 500.000 ;
    END
  END wbs_dat_i[9]
  PIN wbs_dat_o[0]
    DIRECTION OUTPUT ;
    USE SIGNAL ;
    ANTENNADIFFAREA 2.673000 ;
    PORT
      LAYER met2 ;
        RECT 108.650 496.000 108.930 500.000 ;
    END
  END wbs_dat_o[0]
  PIN wbs_dat_o[10]
    DIRECTION OUTPUT ;
    USE SIGNAL ;
    ANTENNADIFFAREA 2.673000 ;
    PORT
      LAYER met2 ;
        RECT 484.010 496.000 484.290 500.000 ;
    END
  END wbs_dat_o[10]
  PIN wbs_dat_o[11]
    DIRECTION OUTPUT ;
    USE SIGNAL ;
    ANTENNADIFFAREA 2.673000 ;
    PORT
      LAYER met2 ;
        RECT 517.130 496.000 517.410 500.000 ;
    END
  END wbs_dat_o[11]
  PIN wbs_dat_o[12]
    DIRECTION OUTPUT ;
    USE SIGNAL ;
    ANTENNADIFFAREA 2.673000 ;
    PORT
      LAYER met2 ;
        RECT 550.250 496.000 550.530 500.000 ;
    END
  END wbs_dat_o[12]
  PIN wbs_dat_o[13]
    DIRECTION OUTPUT ;
    USE SIGNAL ;
    ANTENNADIFFAREA 2.673000 ;
    PORT
      LAYER met2 ;
        RECT 583.370 496.000 583.650 500.000 ;
    END
  END wbs_dat_o[13]
  PIN wbs_dat_o[14]
    DIRECTION OUTPUT ;
    USE SIGNAL ;
    ANTENNADIFFAREA 2.673000 ;
    PORT
      LAYER met2 ;
        RECT 616.490 496.000 616.770 500.000 ;
    END
  END wbs_dat_o[14]
  PIN wbs_dat_o[15]
    DIRECTION OUTPUT ;
    USE SIGNAL ;
    ANTENNADIFFAREA 2.673000 ;
    PORT
      LAYER met2 ;
        RECT 649.610 496.000 649.890 500.000 ;
    END
  END wbs_dat_o[15]
  PIN wbs_dat_o[16]
    DIRECTION OUTPUT ;
    USE SIGNAL ;
    ANTENNADIFFAREA 2.673000 ;
    PORT
      LAYER met2 ;
        RECT 682.730 496.000 683.010 500.000 ;
    END
  END wbs_dat_o[16]
  PIN wbs_dat_o[17]
    DIRECTION OUTPUT ;
    USE SIGNAL ;
    ANTENNADIFFAREA 2.673000 ;
    PORT
      LAYER met2 ;
        RECT 715.850 496.000 716.130 500.000 ;
    END
  END wbs_dat_o[17]
  PIN wbs_dat_o[18]
    DIRECTION OUTPUT ;
    USE SIGNAL ;
    ANTENNADIFFAREA 2.673000 ;
    PORT
      LAYER met2 ;
        RECT 748.970 496.000 749.250 500.000 ;
    END
  END wbs_dat_o[18]
  PIN wbs_dat_o[19]
    DIRECTION OUTPUT ;
    USE SIGNAL ;
    ANTENNADIFFAREA 2.673000 ;
    PORT
      LAYER met2 ;
        RECT 782.090 496.000 782.370 500.000 ;
    END
  END wbs_dat_o[19]
  PIN wbs_dat_o[1]
    DIRECTION OUTPUT ;
    USE SIGNAL ;
    ANTENNADIFFAREA 2.673000 ;
    PORT
      LAYER met2 ;
        RECT 152.810 496.000 153.090 500.000 ;
    END
  END wbs_dat_o[1]
  PIN wbs_dat_o[20]
    DIRECTION OUTPUT ;
    USE SIGNAL ;
    ANTENNADIFFAREA 2.673000 ;
    PORT
      LAYER met2 ;
        RECT 815.210 496.000 815.490 500.000 ;
    END
  END wbs_dat_o[20]
  PIN wbs_dat_o[21]
    DIRECTION OUTPUT ;
    USE SIGNAL ;
    ANTENNADIFFAREA 2.673000 ;
    PORT
      LAYER met2 ;
        RECT 848.330 496.000 848.610 500.000 ;
    END
  END wbs_dat_o[21]
  PIN wbs_dat_o[22]
    DIRECTION OUTPUT ;
    USE SIGNAL ;
    ANTENNADIFFAREA 2.673000 ;
    PORT
      LAYER met2 ;
        RECT 881.450 496.000 881.730 500.000 ;
    END
  END wbs_dat_o[22]
  PIN wbs_dat_o[23]
    DIRECTION OUTPUT ;
    USE SIGNAL ;
    ANTENNADIFFAREA 2.673000 ;
    PORT
      LAYER met2 ;
        RECT 914.570 496.000 914.850 500.000 ;
    END
  END wbs_dat_o[23]
  PIN wbs_dat_o[24]
    DIRECTION OUTPUT ;
    USE SIGNAL ;
    ANTENNADIFFAREA 2.673000 ;
    PORT
      LAYER met2 ;
        RECT 947.690 496.000 947.970 500.000 ;
    END
  END wbs_dat_o[24]
  PIN wbs_dat_o[25]
    DIRECTION OUTPUT ;
    USE SIGNAL ;
    ANTENNADIFFAREA 2.673000 ;
    PORT
      LAYER met2 ;
        RECT 980.810 496.000 981.090 500.000 ;
    END
  END wbs_dat_o[25]
  PIN wbs_dat_o[26]
    DIRECTION OUTPUT ;
    USE SIGNAL ;
    ANTENNADIFFAREA 2.673000 ;
    PORT
      LAYER met2 ;
        RECT 1013.930 496.000 1014.210 500.000 ;
    END
  END wbs_dat_o[26]
  PIN wbs_dat_o[27]
    DIRECTION OUTPUT ;
    USE SIGNAL ;
    ANTENNADIFFAREA 2.673000 ;
    PORT
      LAYER met2 ;
        RECT 1047.050 496.000 1047.330 500.000 ;
    END
  END wbs_dat_o[27]
  PIN wbs_dat_o[28]
    DIRECTION OUTPUT ;
    USE SIGNAL ;
    ANTENNADIFFAREA 2.673000 ;
    PORT
      LAYER met2 ;
        RECT 1080.170 496.000 1080.450 500.000 ;
    END
  END wbs_dat_o[28]
  PIN wbs_dat_o[29]
    DIRECTION OUTPUT ;
    USE SIGNAL ;
    ANTENNADIFFAREA 2.673000 ;
    PORT
      LAYER met2 ;
        RECT 1113.290 496.000 1113.570 500.000 ;
    END
  END wbs_dat_o[29]
  PIN wbs_dat_o[2]
    DIRECTION OUTPUT ;
    USE SIGNAL ;
    ANTENNADIFFAREA 2.673000 ;
    PORT
      LAYER met2 ;
        RECT 196.970 496.000 197.250 500.000 ;
    END
  END wbs_dat_o[2]
  PIN wbs_dat_o[30]
    DIRECTION OUTPUT ;
    USE SIGNAL ;
    ANTENNADIFFAREA 2.673000 ;
    PORT
      LAYER met2 ;
        RECT 1146.410 496.000 1146.690 500.000 ;
    END
  END wbs_dat_o[30]
  PIN wbs_dat_o[31]
    DIRECTION OUTPUT ;
    USE SIGNAL ;
    ANTENNADIFFAREA 2.673000 ;
    PORT
      LAYER met2 ;
        RECT 1179.530 496.000 1179.810 500.000 ;
    END
  END wbs_dat_o[31]
  PIN wbs_dat_o[3]
    DIRECTION OUTPUT ;
    USE SIGNAL ;
    ANTENNADIFFAREA 2.673000 ;
    PORT
      LAYER met2 ;
        RECT 241.130 496.000 241.410 500.000 ;
    END
  END wbs_dat_o[3]
  PIN wbs_dat_o[4]
    DIRECTION OUTPUT ;
    USE SIGNAL ;
    ANTENNADIFFAREA 2.673000 ;
    PORT
      LAYER met2 ;
        RECT 285.290 496.000 285.570 500.000 ;
    END
  END wbs_dat_o[4]
  PIN wbs_dat_o[5]
    DIRECTION OUTPUT ;
    USE SIGNAL ;
    ANTENNADIFFAREA 2.673000 ;
    PORT
      LAYER met2 ;
        RECT 318.410 496.000 318.690 500.000 ;
    END
  END wbs_dat_o[5]
  PIN wbs_dat_o[6]
    DIRECTION OUTPUT ;
    USE SIGNAL ;
    ANTENNADIFFAREA 2.673000 ;
    PORT
      LAYER met2 ;
        RECT 351.530 496.000 351.810 500.000 ;
    END
  END wbs_dat_o[6]
  PIN wbs_dat_o[7]
    DIRECTION OUTPUT ;
    USE SIGNAL ;
    ANTENNADIFFAREA 2.673000 ;
    PORT
      LAYER met2 ;
        RECT 384.650 496.000 384.930 500.000 ;
    END
  END wbs_dat_o[7]
  PIN wbs_dat_o[8]
    DIRECTION OUTPUT ;
    USE SIGNAL ;
    ANTENNADIFFAREA 2.673000 ;
    PORT
      LAYER met2 ;
        RECT 417.770 496.000 418.050 500.000 ;
    END
  END wbs_dat_o[8]
  PIN wbs_dat_o[9]
    DIRECTION OUTPUT ;
    USE SIGNAL ;
    ANTENNADIFFAREA 2.673000 ;
    PORT
      LAYER met2 ;
        RECT 450.890 496.000 451.170 500.000 ;
    END
  END wbs_dat_o[9]
  PIN wbs_sel_i[0]
    DIRECTION INPUT ;
    USE SIGNAL ;
    ANTENNAGATEAREA 0.126000 ;
    PORT
      LAYER met2 ;
        RECT 119.690 496.000 119.970 500.000 ;
    END
  END wbs_sel_i[0]
  PIN wbs_sel_i[1]
    DIRECTION INPUT ;
    USE SIGNAL ;
    ANTENNAGATEAREA 0.126000 ;
    PORT
      LAYER met2 ;
        RECT 163.850 496.000 164.130 500.000 ;
    END
  END wbs_sel_i[1]
  PIN wbs_sel_i[2]
    DIRECTION INPUT ;
    USE SIGNAL ;
    PORT
      LAYER met2 ;
        RECT 208.010 496.000 208.290 500.000 ;
    END
  END wbs_sel_i[2]
  PIN wbs_sel_i[3]
    DIRECTION INPUT ;
    USE SIGNAL ;
    PORT
      LAYER met2 ;
        RECT 252.170 496.000 252.450 500.000 ;
    END
  END wbs_sel_i[3]
  PIN wbs_stb_i
    DIRECTION INPUT ;
    USE SIGNAL ;
    ANTENNAGATEAREA 0.742500 ;
    PORT
      LAYER met2 ;
        RECT 64.490 496.000 64.770 500.000 ;
    END
  END wbs_stb_i
  PIN wbs_we_i
    DIRECTION INPUT ;
    USE SIGNAL ;
    ANTENNAGATEAREA 0.126000 ;
    PORT
      LAYER met2 ;
        RECT 75.530 496.000 75.810 500.000 ;
    END
  END wbs_we_i
  OBS
      LAYER nwell ;
        RECT 5.330 10.760 1194.350 487.070 ;
      LAYER li1 ;
        RECT 5.520 10.795 1194.160 486.965 ;
      LAYER met1 ;
        RECT 4.210 10.240 1195.470 497.040 ;
      LAYER met2 ;
        RECT 4.230 495.720 20.050 497.490 ;
        RECT 20.890 495.720 31.090 497.490 ;
        RECT 31.930 495.720 42.130 497.490 ;
        RECT 42.970 495.720 53.170 497.490 ;
        RECT 54.010 495.720 64.210 497.490 ;
        RECT 65.050 495.720 75.250 497.490 ;
        RECT 76.090 495.720 86.290 497.490 ;
        RECT 87.130 495.720 97.330 497.490 ;
        RECT 98.170 495.720 108.370 497.490 ;
        RECT 109.210 495.720 119.410 497.490 ;
        RECT 120.250 495.720 130.450 497.490 ;
        RECT 131.290 495.720 141.490 497.490 ;
        RECT 142.330 495.720 152.530 497.490 ;
        RECT 153.370 495.720 163.570 497.490 ;
        RECT 164.410 495.720 174.610 497.490 ;
        RECT 175.450 495.720 185.650 497.490 ;
        RECT 186.490 495.720 196.690 497.490 ;
        RECT 197.530 495.720 207.730 497.490 ;
        RECT 208.570 495.720 218.770 497.490 ;
        RECT 219.610 495.720 229.810 497.490 ;
        RECT 230.650 495.720 240.850 497.490 ;
        RECT 241.690 495.720 251.890 497.490 ;
        RECT 252.730 495.720 262.930 497.490 ;
        RECT 263.770 495.720 273.970 497.490 ;
        RECT 274.810 495.720 285.010 497.490 ;
        RECT 285.850 495.720 296.050 497.490 ;
        RECT 296.890 495.720 307.090 497.490 ;
        RECT 307.930 495.720 318.130 497.490 ;
        RECT 318.970 495.720 329.170 497.490 ;
        RECT 330.010 495.720 340.210 497.490 ;
        RECT 341.050 495.720 351.250 497.490 ;
        RECT 352.090 495.720 362.290 497.490 ;
        RECT 363.130 495.720 373.330 497.490 ;
        RECT 374.170 495.720 384.370 497.490 ;
        RECT 385.210 495.720 395.410 497.490 ;
        RECT 396.250 495.720 406.450 497.490 ;
        RECT 407.290 495.720 417.490 497.490 ;
        RECT 418.330 495.720 428.530 497.490 ;
        RECT 429.370 495.720 439.570 497.490 ;
        RECT 440.410 495.720 450.610 497.490 ;
        RECT 451.450 495.720 461.650 497.490 ;
        RECT 462.490 495.720 472.690 497.490 ;
        RECT 473.530 495.720 483.730 497.490 ;
        RECT 484.570 495.720 494.770 497.490 ;
        RECT 495.610 495.720 505.810 497.490 ;
        RECT 506.650 495.720 516.850 497.490 ;
        RECT 517.690 495.720 527.890 497.490 ;
        RECT 528.730 495.720 538.930 497.490 ;
        RECT 539.770 495.720 549.970 497.490 ;
        RECT 550.810 495.720 561.010 497.490 ;
        RECT 561.850 495.720 572.050 497.490 ;
        RECT 572.890 495.720 583.090 497.490 ;
        RECT 583.930 495.720 594.130 497.490 ;
        RECT 594.970 495.720 605.170 497.490 ;
        RECT 606.010 495.720 616.210 497.490 ;
        RECT 617.050 495.720 627.250 497.490 ;
        RECT 628.090 495.720 638.290 497.490 ;
        RECT 639.130 495.720 649.330 497.490 ;
        RECT 650.170 495.720 660.370 497.490 ;
        RECT 661.210 495.720 671.410 497.490 ;
        RECT 672.250 495.720 682.450 497.490 ;
        RECT 683.290 495.720 693.490 497.490 ;
        RECT 694.330 495.720 704.530 497.490 ;
        RECT 705.370 495.720 715.570 497.490 ;
        RECT 716.410 495.720 726.610 497.490 ;
        RECT 727.450 495.720 737.650 497.490 ;
        RECT 738.490 495.720 748.690 497.490 ;
        RECT 749.530 495.720 759.730 497.490 ;
        RECT 760.570 495.720 770.770 497.490 ;
        RECT 771.610 495.720 781.810 497.490 ;
        RECT 782.650 495.720 792.850 497.490 ;
        RECT 793.690 495.720 803.890 497.490 ;
        RECT 804.730 495.720 814.930 497.490 ;
        RECT 815.770 495.720 825.970 497.490 ;
        RECT 826.810 495.720 837.010 497.490 ;
        RECT 837.850 495.720 848.050 497.490 ;
        RECT 848.890 495.720 859.090 497.490 ;
        RECT 859.930 495.720 870.130 497.490 ;
        RECT 870.970 495.720 881.170 497.490 ;
        RECT 882.010 495.720 892.210 497.490 ;
        RECT 893.050 495.720 903.250 497.490 ;
        RECT 904.090 495.720 914.290 497.490 ;
        RECT 915.130 495.720 925.330 497.490 ;
        RECT 926.170 495.720 936.370 497.490 ;
        RECT 937.210 495.720 947.410 497.490 ;
        RECT 948.250 495.720 958.450 497.490 ;
        RECT 959.290 495.720 969.490 497.490 ;
        RECT 970.330 495.720 980.530 497.490 ;
        RECT 981.370 495.720 991.570 497.490 ;
        RECT 992.410 495.720 1002.610 497.490 ;
        RECT 1003.450 495.720 1013.650 497.490 ;
        RECT 1014.490 495.720 1024.690 497.490 ;
        RECT 1025.530 495.720 1035.730 497.490 ;
        RECT 1036.570 495.720 1046.770 497.490 ;
        RECT 1047.610 495.720 1057.810 497.490 ;
        RECT 1058.650 495.720 1068.850 497.490 ;
        RECT 1069.690 495.720 1079.890 497.490 ;
        RECT 1080.730 495.720 1090.930 497.490 ;
        RECT 1091.770 495.720 1101.970 497.490 ;
        RECT 1102.810 495.720 1113.010 497.490 ;
        RECT 1113.850 495.720 1124.050 497.490 ;
        RECT 1124.890 495.720 1135.090 497.490 ;
        RECT 1135.930 495.720 1146.130 497.490 ;
        RECT 1146.970 495.720 1157.170 497.490 ;
        RECT 1158.010 495.720 1168.210 497.490 ;
        RECT 1169.050 495.720 1179.250 497.490 ;
        RECT 1180.090 495.720 1195.450 497.490 ;
        RECT 4.230 4.280 1195.450 495.720 ;
        RECT 4.230 4.000 37.070 4.280 ;
        RECT 37.910 4.000 112.050 4.280 ;
        RECT 112.890 4.000 187.030 4.280 ;
        RECT 187.870 4.000 262.010 4.280 ;
        RECT 262.850 4.000 336.990 4.280 ;
        RECT 337.830 4.000 411.970 4.280 ;
        RECT 412.810 4.000 486.950 4.280 ;
        RECT 487.790 4.000 561.930 4.280 ;
        RECT 562.770 4.000 636.910 4.280 ;
        RECT 637.750 4.000 711.890 4.280 ;
        RECT 712.730 4.000 786.870 4.280 ;
        RECT 787.710 4.000 861.850 4.280 ;
        RECT 862.690 4.000 936.830 4.280 ;
        RECT 937.670 4.000 1011.810 4.280 ;
        RECT 1012.650 4.000 1086.790 4.280 ;
        RECT 1087.630 4.000 1161.770 4.280 ;
        RECT 1162.610 4.000 1195.450 4.280 ;
      LAYER met3 ;
        RECT 3.990 437.600 1196.000 487.045 ;
        RECT 4.400 436.200 1196.000 437.600 ;
        RECT 3.990 433.520 1196.000 436.200 ;
        RECT 4.400 432.120 1196.000 433.520 ;
        RECT 3.990 429.440 1196.000 432.120 ;
        RECT 4.400 428.040 1196.000 429.440 ;
        RECT 3.990 425.360 1196.000 428.040 ;
        RECT 4.400 423.960 1196.000 425.360 ;
        RECT 3.990 421.280 1196.000 423.960 ;
        RECT 4.400 419.880 1196.000 421.280 ;
        RECT 3.990 417.200 1196.000 419.880 ;
        RECT 4.400 415.800 1196.000 417.200 ;
        RECT 3.990 413.120 1196.000 415.800 ;
        RECT 4.400 411.720 1196.000 413.120 ;
        RECT 3.990 409.040 1196.000 411.720 ;
        RECT 4.400 407.640 1196.000 409.040 ;
        RECT 3.990 404.960 1196.000 407.640 ;
        RECT 4.400 403.600 1196.000 404.960 ;
        RECT 4.400 403.560 1195.600 403.600 ;
        RECT 3.990 400.880 1195.600 403.560 ;
        RECT 4.400 399.480 1195.600 400.880 ;
        RECT 3.990 396.800 1195.600 399.480 ;
        RECT 4.400 395.400 1195.600 396.800 ;
        RECT 3.990 392.720 1195.600 395.400 ;
        RECT 4.400 391.320 1195.600 392.720 ;
        RECT 3.990 388.640 1195.600 391.320 ;
        RECT 4.400 387.240 1195.600 388.640 ;
        RECT 3.990 384.560 1195.600 387.240 ;
        RECT 4.400 383.160 1195.600 384.560 ;
        RECT 3.990 380.480 1195.600 383.160 ;
        RECT 4.400 379.080 1195.600 380.480 ;
        RECT 3.990 376.400 1195.600 379.080 ;
        RECT 4.400 375.000 1195.600 376.400 ;
        RECT 3.990 372.320 1195.600 375.000 ;
        RECT 4.400 370.920 1195.600 372.320 ;
        RECT 3.990 368.240 1195.600 370.920 ;
        RECT 4.400 366.840 1195.600 368.240 ;
        RECT 3.990 364.160 1195.600 366.840 ;
        RECT 4.400 362.760 1195.600 364.160 ;
        RECT 3.990 360.080 1195.600 362.760 ;
        RECT 4.400 358.680 1195.600 360.080 ;
        RECT 3.990 356.000 1195.600 358.680 ;
        RECT 4.400 354.600 1195.600 356.000 ;
        RECT 3.990 351.920 1195.600 354.600 ;
        RECT 4.400 350.520 1195.600 351.920 ;
        RECT 3.990 347.840 1195.600 350.520 ;
        RECT 4.400 346.440 1195.600 347.840 ;
        RECT 3.990 343.760 1195.600 346.440 ;
        RECT 4.400 342.360 1195.600 343.760 ;
        RECT 3.990 339.680 1195.600 342.360 ;
        RECT 4.400 338.280 1195.600 339.680 ;
        RECT 3.990 335.600 1195.600 338.280 ;
        RECT 4.400 334.200 1195.600 335.600 ;
        RECT 3.990 331.520 1195.600 334.200 ;
        RECT 4.400 330.120 1195.600 331.520 ;
        RECT 3.990 327.440 1195.600 330.120 ;
        RECT 4.400 326.040 1195.600 327.440 ;
        RECT 3.990 323.360 1195.600 326.040 ;
        RECT 4.400 321.960 1195.600 323.360 ;
        RECT 3.990 319.280 1195.600 321.960 ;
        RECT 4.400 317.880 1195.600 319.280 ;
        RECT 3.990 315.200 1195.600 317.880 ;
        RECT 4.400 313.800 1195.600 315.200 ;
        RECT 3.990 311.120 1195.600 313.800 ;
        RECT 4.400 309.720 1195.600 311.120 ;
        RECT 3.990 307.040 1195.600 309.720 ;
        RECT 4.400 305.640 1195.600 307.040 ;
        RECT 3.990 302.960 1195.600 305.640 ;
        RECT 4.400 301.560 1195.600 302.960 ;
        RECT 3.990 298.880 1195.600 301.560 ;
        RECT 4.400 297.480 1195.600 298.880 ;
        RECT 3.990 294.800 1195.600 297.480 ;
        RECT 4.400 293.400 1195.600 294.800 ;
        RECT 3.990 290.720 1195.600 293.400 ;
        RECT 4.400 289.320 1195.600 290.720 ;
        RECT 3.990 286.640 1195.600 289.320 ;
        RECT 4.400 285.240 1195.600 286.640 ;
        RECT 3.990 282.560 1195.600 285.240 ;
        RECT 4.400 281.160 1195.600 282.560 ;
        RECT 3.990 278.480 1195.600 281.160 ;
        RECT 4.400 277.080 1195.600 278.480 ;
        RECT 3.990 274.400 1195.600 277.080 ;
        RECT 4.400 273.000 1195.600 274.400 ;
        RECT 3.990 270.320 1195.600 273.000 ;
        RECT 4.400 268.920 1195.600 270.320 ;
        RECT 3.990 266.240 1195.600 268.920 ;
        RECT 4.400 264.840 1195.600 266.240 ;
        RECT 3.990 262.160 1195.600 264.840 ;
        RECT 4.400 260.760 1195.600 262.160 ;
        RECT 3.990 258.080 1195.600 260.760 ;
        RECT 4.400 256.680 1195.600 258.080 ;
        RECT 3.990 254.000 1195.600 256.680 ;
        RECT 4.400 252.600 1195.600 254.000 ;
        RECT 3.990 249.920 1195.600 252.600 ;
        RECT 4.400 248.520 1195.600 249.920 ;
        RECT 3.990 245.840 1195.600 248.520 ;
        RECT 4.400 244.440 1195.600 245.840 ;
        RECT 3.990 241.760 1195.600 244.440 ;
        RECT 4.400 240.360 1195.600 241.760 ;
        RECT 3.990 237.680 1195.600 240.360 ;
        RECT 4.400 236.280 1195.600 237.680 ;
        RECT 3.990 233.600 1195.600 236.280 ;
        RECT 4.400 232.200 1195.600 233.600 ;
        RECT 3.990 229.520 1195.600 232.200 ;
        RECT 4.400 228.120 1195.600 229.520 ;
        RECT 3.990 225.440 1195.600 228.120 ;
        RECT 4.400 224.040 1195.600 225.440 ;
        RECT 3.990 221.360 1195.600 224.040 ;
        RECT 4.400 219.960 1195.600 221.360 ;
        RECT 3.990 217.280 1195.600 219.960 ;
        RECT 4.400 215.880 1195.600 217.280 ;
        RECT 3.990 213.200 1195.600 215.880 ;
        RECT 4.400 211.800 1195.600 213.200 ;
        RECT 3.990 209.120 1195.600 211.800 ;
        RECT 4.400 207.720 1195.600 209.120 ;
        RECT 3.990 205.040 1195.600 207.720 ;
        RECT 4.400 203.640 1195.600 205.040 ;
        RECT 3.990 200.960 1195.600 203.640 ;
        RECT 4.400 199.560 1195.600 200.960 ;
        RECT 3.990 196.880 1195.600 199.560 ;
        RECT 4.400 195.480 1195.600 196.880 ;
        RECT 3.990 192.800 1195.600 195.480 ;
        RECT 4.400 191.400 1195.600 192.800 ;
        RECT 3.990 188.720 1195.600 191.400 ;
        RECT 4.400 187.320 1195.600 188.720 ;
        RECT 3.990 184.640 1195.600 187.320 ;
        RECT 4.400 183.240 1195.600 184.640 ;
        RECT 3.990 180.560 1195.600 183.240 ;
        RECT 4.400 179.160 1195.600 180.560 ;
        RECT 3.990 176.480 1195.600 179.160 ;
        RECT 4.400 175.080 1195.600 176.480 ;
        RECT 3.990 172.400 1195.600 175.080 ;
        RECT 4.400 171.000 1195.600 172.400 ;
        RECT 3.990 168.320 1195.600 171.000 ;
        RECT 4.400 166.920 1195.600 168.320 ;
        RECT 3.990 164.240 1195.600 166.920 ;
        RECT 4.400 162.840 1195.600 164.240 ;
        RECT 3.990 160.160 1195.600 162.840 ;
        RECT 4.400 158.760 1195.600 160.160 ;
        RECT 3.990 156.080 1195.600 158.760 ;
        RECT 4.400 154.680 1195.600 156.080 ;
        RECT 3.990 152.000 1195.600 154.680 ;
        RECT 4.400 150.600 1195.600 152.000 ;
        RECT 3.990 147.920 1195.600 150.600 ;
        RECT 4.400 146.520 1195.600 147.920 ;
        RECT 3.990 143.840 1195.600 146.520 ;
        RECT 4.400 142.440 1195.600 143.840 ;
        RECT 3.990 139.760 1195.600 142.440 ;
        RECT 4.400 138.360 1195.600 139.760 ;
        RECT 3.990 135.680 1195.600 138.360 ;
        RECT 4.400 134.280 1195.600 135.680 ;
        RECT 3.990 131.600 1195.600 134.280 ;
        RECT 4.400 130.200 1195.600 131.600 ;
        RECT 3.990 127.520 1195.600 130.200 ;
        RECT 4.400 126.120 1195.600 127.520 ;
        RECT 3.990 123.440 1195.600 126.120 ;
        RECT 4.400 122.040 1195.600 123.440 ;
        RECT 3.990 119.360 1195.600 122.040 ;
        RECT 4.400 117.960 1195.600 119.360 ;
        RECT 3.990 115.280 1195.600 117.960 ;
        RECT 4.400 113.880 1195.600 115.280 ;
        RECT 3.990 111.200 1195.600 113.880 ;
        RECT 4.400 109.800 1195.600 111.200 ;
        RECT 3.990 107.120 1195.600 109.800 ;
        RECT 4.400 105.720 1195.600 107.120 ;
        RECT 3.990 103.040 1195.600 105.720 ;
        RECT 4.400 101.640 1195.600 103.040 ;
        RECT 3.990 98.960 1195.600 101.640 ;
        RECT 4.400 97.560 1195.600 98.960 ;
        RECT 3.990 94.880 1195.600 97.560 ;
        RECT 4.400 94.840 1195.600 94.880 ;
        RECT 4.400 93.480 1196.000 94.840 ;
        RECT 3.990 90.800 1196.000 93.480 ;
        RECT 4.400 89.400 1196.000 90.800 ;
        RECT 3.990 86.720 1196.000 89.400 ;
        RECT 4.400 85.320 1196.000 86.720 ;
        RECT 3.990 82.640 1196.000 85.320 ;
        RECT 4.400 81.240 1196.000 82.640 ;
        RECT 3.990 78.560 1196.000 81.240 ;
        RECT 4.400 77.160 1196.000 78.560 ;
        RECT 3.990 74.480 1196.000 77.160 ;
        RECT 4.400 73.080 1196.000 74.480 ;
        RECT 3.990 70.400 1196.000 73.080 ;
        RECT 4.400 69.000 1196.000 70.400 ;
        RECT 3.990 66.320 1196.000 69.000 ;
        RECT 4.400 64.920 1196.000 66.320 ;
        RECT 3.990 62.240 1196.000 64.920 ;
        RECT 4.400 60.840 1196.000 62.240 ;
        RECT 3.990 10.715 1196.000 60.840 ;
  END
END soc_sys
END LIBRARY

